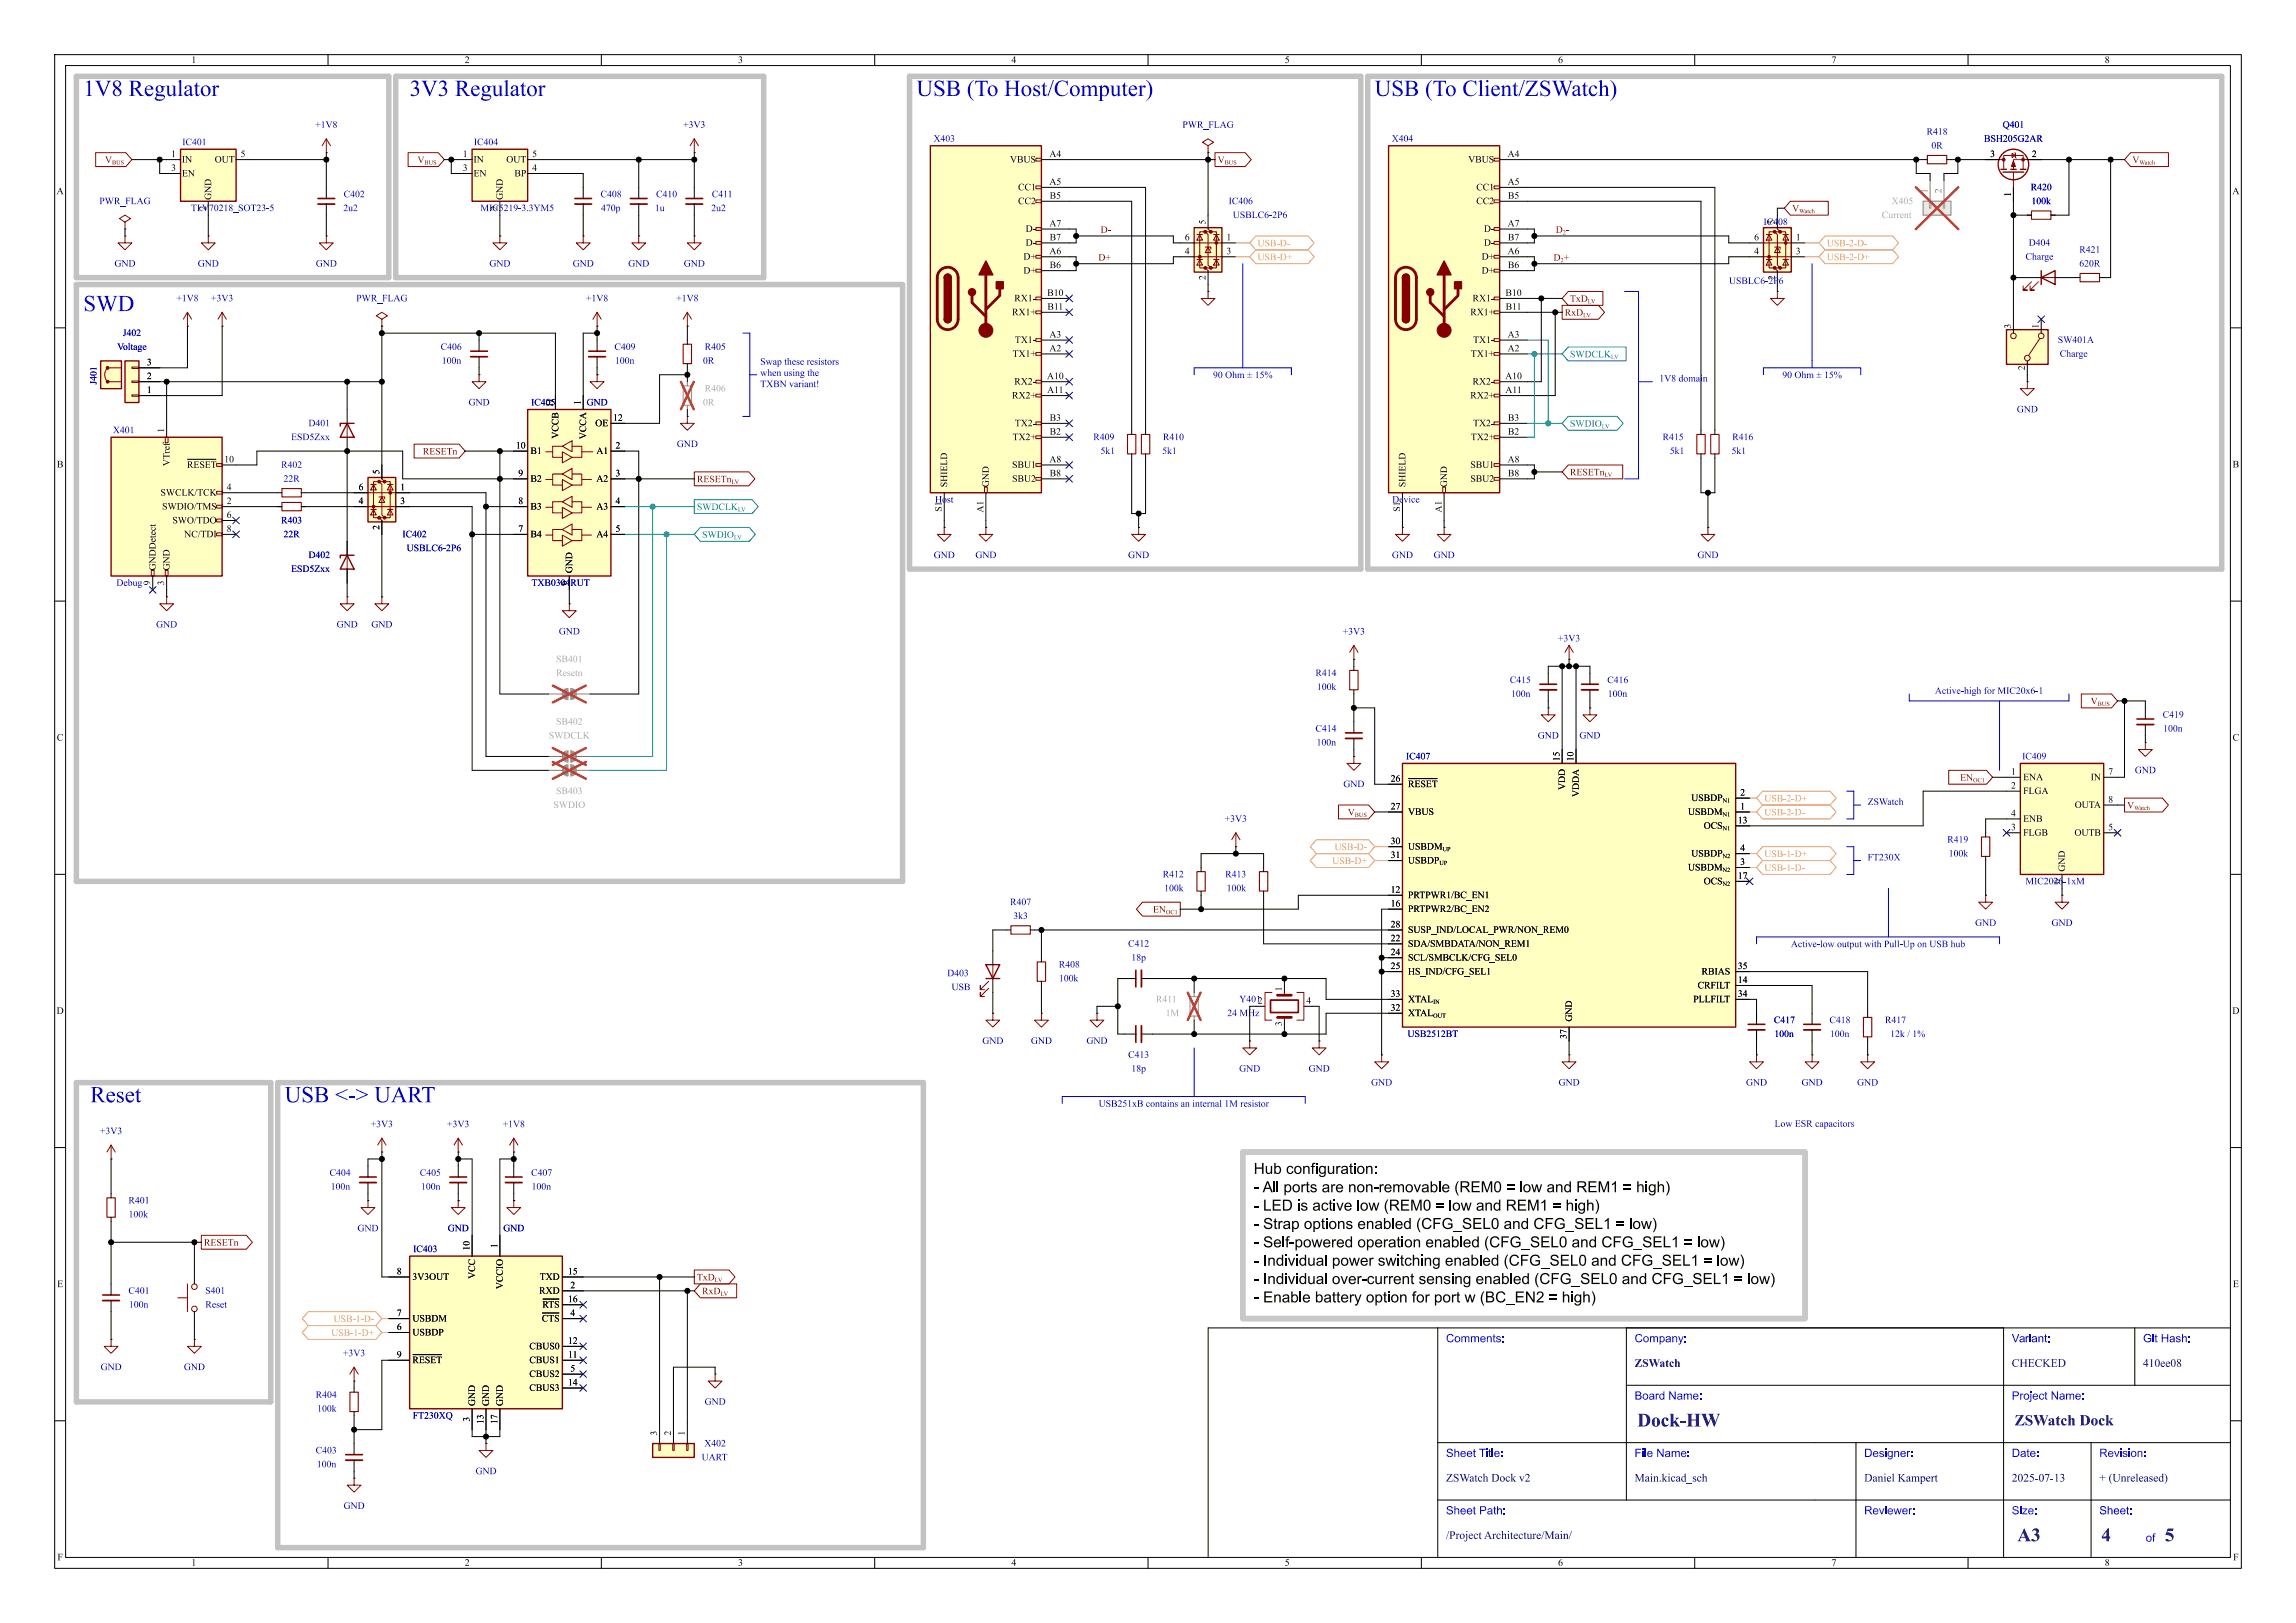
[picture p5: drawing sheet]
<svg xmlns="http://www.w3.org/2000/svg" width="420mm" height="297mm" viewBox="0 0 420 297" stroke-linecap="round" stroke-linejoin="round" font-family="sans-serif">
<defs><g id="words">
<g font-size="4.2" fill="#0000c2">
<text x="15.2" y="18.1">1V8 Regulator</text>
<text x="74.9" y="18.1">3V3 Regulator</text>
<text x="167.6" y="18.1">USB(ToHost/Computer)</text>
<text x="251.5" y="18.1">USB(ToClient/ZSWatch)</text>
<text x="15.2" y="57.4">SWD</text>
<text x="16.5" y="202.2">Reset</text>
<text x="52.1" y="202.2">USB&lt;-&gt; UART</text>
</g>
<g font-size="3.5" fill="#00007f">
<text x="299.5" y="261.9">Dock-HW</text>
<text x="369" y="282.9">A3</text>
<text x="384.4" y="282.9">4</text>
<text x="396" y="282.9">5</text>
</g>
<g font-size="2.8">
<text x="229.3" y="216">Hub configuration:</text>
<text x="229.3" y="219.3">- All ports are non-removable (REM0 = low and REM1 = high)</text>
<text x="229.3" y="229.4">- Self-powered operation enabled (CFG_SEL0 and CFG_SEL1 = low)</text>
<text x="229.3" y="236.1">- Individual over-current sensing enabled (CFG_SEL0 and CFG_SEL1 = low)</text>
</g>
<text font-size="2.8" fill="#00007f" x="368.5" y="261.6">ZSWatchDock</text>
<g font-size="2.1" fill="#00f">
<text x="264.5" y="246.2">Comments:</text>
<text x="299" y="246.2">Company:</text>
<text x="368" y="246.2">Variant:</text>
<text x="392" y="246.2">Git Hash:</text>
<text x="299" y="256.7">Board Name:</text>
<text x="368" y="256.7">Project Name:</text>
<text x="264.5" y="267.2">Sheet Title:</text>
<text x="299" y="267.2">File Name:</text>
<text x="341" y="267.2">Designer:</text>
<text x="368" y="267.2">Date:</text>
<text x="384" y="267.2">Revision:</text>
<text x="264.5" y="277.7">Sheet Path:</text>
<text x="341" y="277.7">Reviewer:</text>
<text x="368" y="277.7">Size:</text>
<text x="384" y="277.7">Sheet:</text>
<text x="392.5" y="282.7">of</text>
</g>
<g font-size="2.1" fill="#00007f">
<text x="299" y="250.7">ZSWatch</text>
<text x="368" y="250.7">CHECKED</text>
<text x="392" y="250.7">410ee08</text>
<text x="264.5" y="271.7">ZSWatchDockv2</text>
<text x="299" y="271.7">Main.kicad_sch</text>
<text x="341" y="271.7">DanielKampert</text>
<text x="368" y="271.7">2025-07-13</text>
<text x="384" y="271.7">+ (Unreleased)</text>
<text x="264.5" y="282.2">/ProjectArchitecture/Main/</text>
</g>
<g font-size="1.8">
<text x="35" y="12">1</text>
<text x="85" y="12">2</text>
<text x="135" y="12">3</text>
<text x="185" y="12">4</text>
<text x="235" y="12">5</text>
<text x="285" y="12">6</text>
<text x="335" y="12">7</text>
<text x="385" y="12">8</text>
<text x="31.3" y="29">1</text>
<text x="44" y="29">5</text>
<text x="84.6" y="29">1</text>
<text x="97.3" y="29">5</text>
<text x="192" y="29">A4</text>
<text x="275.8" y="29">A4</text>
<text x="364" y="29">3</text>
<text x="371.7" y="29">2</text>
<text x="31.3" y="31.5">3</text>
<text x="33.3" y="30.2">IN</text>
<text x="33.3" y="32.7">EN</text>
<text x="39.3" y="30.2">OUT</text>
<text x="76.4" y="30.3">V_{BUS}</text>
<text x="84.6" y="31.5">3</text>
<text x="86.6" y="30.2">IN</text>
<text x="86.6" y="32.7">EN</text>
<text x="92.6" y="30.2">OUT</text>
<text x="94.1" y="32.7">BP</text>
<text x="97.3" y="31.5">4</text>
<text x="184.7" y="30.2">VBUS</text>
<text x="186.2" y="35.3">CC1</text>
<text x="192" y="34">A5</text>
<text x="268.6" y="30.2">VBUS</text>
<text x="270" y="35.3">CC1</text>
<text x="275.8" y="34">A5</text>
<text x="10.3" y="36">A</text>
<text x="39.1" y="36.6" transform="rotate(-90 39.1 36.6)">GND</text>
<text x="92.4" y="36.6" transform="rotate(-90 92.4 36.6)">GND</text>
<text x="186.2" y="37.8">CC2</text>
<text x="192" y="41.7">A7</text>
<text x="192" y="36.6">B5</text>
<text x="220.7" y="41.1" transform="rotate(-90 220.7 41.1)">5</text>
<text x="270" y="37.8">CC2</text>
<text x="275.8" y="41.7">A7</text>
<text x="275.8" y="36.6">B5</text>
<text x="368" y="36" transform="rotate(-90 368 36)">1</text>
<text x="408.3" y="36">A</text>
<text x="187.2" y="48">D+</text>
<text x="187.6" y="42.9">D-</text>
<text x="187.6" y="45.4">D-</text>
<text x="192" y="46.7">A6</text>
<text x="192" y="44.2">B7</text>
<text x="216.7" y="44.2">6</text>
<text x="216.7" y="46.7">4</text>
<text x="224.3" y="44.2">1</text>
<text x="224.3" y="46.7">3</text>
<text x="271" y="48">D+</text>
<text x="271.4" y="42.9">D-</text>
<text x="271.4" y="45.4">D-</text>
<text x="275.8" y="46.7">A6</text>
<text x="275.8" y="44.2">B7</text>
<text x="320.9" y="44.2">6</text>
<text x="320.9" y="46.7">4</text>
<text x="328.5" y="44.2">1</text>
<text x="328.5" y="46.7">3</text>
<text x="187.2" y="50.5">D+</text>
<text x="192" y="49.3">B6</text>
<text x="220.7" y="51.2" transform="rotate(-90 220.7 51.2)">2</text>
<text x="271" y="50.5">D+</text>
<text x="275.8" y="49.3">B6</text>
<text x="324.9" y="51.2" transform="rotate(-90 324.9 51.2)">2</text>
<text x="185.1" y="58.1">RX1+</text>
<text x="185.5" y="55.6">RX1-</text>
<text x="191.6" y="54.4">B10</text>
<text x="191.6" y="56.9">B11</text>
<text x="268.9" y="58.1">RX1+</text>
<text x="269.4" y="55.6">RX1-</text>
<text x="275.4" y="54.4">B10</text>
<text x="275.4" y="56.9">B11</text>
<text x="185.2" y="65.8">TX1+</text>
<text x="185.6" y="63.2">TX1-</text>
<text x="192" y="62">A3</text>
<text x="192" y="64.5">A2</text>
<text x="269" y="65.8">TX1+</text>
<text x="269.5" y="63.2">TX1-</text>
<text x="275.8" y="62">A3</text>
<text x="275.8" y="64.5">A2</text>
<text x="368" y="60.1" transform="rotate(-90 368 60.1)">3</text>
<text x="373.1" y="60.1" transform="rotate(-90 373.1 60.1)">1</text>
<text x="26.9" y="69.6">2</text>
<text x="26.9" y="67.1">3</text>
<text x="185.5" y="70.8">RX2-</text>
<text x="191.5" y="69.6">A10</text>
<text x="269.4" y="70.8">RX2-</text>
<text x="275.3" y="69.6">A10</text>
<text x="370.6" y="67.8" transform="rotate(-90 370.6 67.8)">2</text>
<text x="26.9" y="72.1">1</text>
<text x="101.3" y="74.5" transform="rotate(-90 101.3 74.5)">11</text>
<text x="106.4" y="74.1" transform="rotate(-90 106.4 74.1)">1</text>
<text x="112.1" y="77.2">12</text>
<text x="185.1" y="73.4">RX2+</text>
<text x="191.5" y="72.1">A11</text>
<text x="192" y="77.2">B3</text>
<text x="268.9" y="73.4">RX2+</text>
<text x="275.4" y="72.1">A11</text>
<text x="275.8" y="77.2">B3</text>
<text x="30.2" y="79.2" transform="rotate(-90 30.2 79.2)">1</text>
<text x="94.4" y="82.3">10</text>
<text x="97" y="83.5">B1</text>
<text x="102.6" y="80.3" transform="rotate(-90 102.6 80.3)">VCCB</text>
<text x="107.7" y="80.4" transform="rotate(-90 107.7 80.4)">VCCA</text>
<text x="108.9" y="78.5">OE</text>
<text x="109.1" y="83.5">A1</text>
<text x="112.6" y="82.3">2</text>
<text x="185.2" y="81">TX2+</text>
<text x="185.6" y="78.5">TX2-</text>
<text x="192" y="79.8">B2</text>
<text x="269" y="81">TX2+</text>
<text x="269.5" y="78.5">TX2-</text>
<text x="275.8" y="79.8">B2</text>
<text x="10.4" y="86">B</text>
<text x="31.5" y="85.3" transform="rotate(-90 31.5 85.3)">VTref</text>
<text x="34.2" y="86.1">~{RESET}</text>
<text x="41" y="84.8">10</text>
<text x="41.5" y="89.9">4</text>
<text x="65.6" y="89.9">6</text>
<text x="69.6" y="86.8" transform="rotate(-90 69.6 86.8)">5</text>
<text x="73.2" y="89.9">1</text>
<text x="94.8" y="87.4">9</text>
<text x="97" y="88.6">B2</text>
<text x="109.1" y="88.6">A2</text>
<text x="112.6" y="87.4">3</text>
<text x="173.7" y="89.2" transform="rotate(-90 173.7 89.2)">SHIELD</text>
<text x="181.3" y="89.2" transform="rotate(-90 181.3 89.2)">GND</text>
<text x="185.1" y="86.1">SBU1</text>
<text x="185.1" y="88.6">SBU2</text>
<text x="192" y="84.8">A8</text>
<text x="192" y="87.4">B8</text>
<text x="257.5" y="89.2" transform="rotate(-90 257.5 89.2)">SHIELD</text>
<text x="265.1" y="89.2" transform="rotate(-90 265.1 89.2)">GND</text>
<text x="269" y="86.1">SBU1</text>
<text x="269" y="88.6">SBU2</text>
<text x="275.8" y="84.8">A8</text>
<text x="275.8" y="87.4">B8</text>
<text x="408.4" y="86">B</text>
<text x="29.4" y="91.2">SWCLK/TCK</text>
<text x="29.7" y="93.7">SWDIO/TMS</text>
<text x="41.5" y="92.5">2</text>
<text x="41.5" y="95">6</text>
<text x="65.6" y="92.5">4</text>
<text x="73.2" y="92.5">3</text>
<text x="94.8" y="92.5">8</text>
<text x="97" y="93.7">B3</text>
<text x="109.1" y="93.7">A3</text>
<text x="112.6" y="92.5">4</text>
<text x="172.5" y="93.6" transform="rotate(-90 172.5 93.6)">S1</text>
<text x="180.1" y="93.8" transform="rotate(-90 180.1 93.8)">A1</text>
<text x="256.3" y="93.6" transform="rotate(-90 256.3 93.6)">S1</text>
<text x="263.9" y="93.8" transform="rotate(-90 263.9 93.8)">A1</text>
<text x="31.5" y="96.2">SWO/TDO</text>
<text x="33.7" y="98.8">NC/TDI</text>
<text x="41.5" y="97.5">8</text>
<text x="69.6" y="97" transform="rotate(-90 69.6 97)">2</text>
<text x="94.8" y="97.5">7</text>
<text x="97" y="98.8">B4</text>
<text x="109.1" y="98.8">A4</text>
<text x="112.6" y="97.5">5</text>
<text x="27.7" y="107.1" transform="rotate(-90 27.7 107.1)">9</text>
<text x="28.9" y="104.4" transform="rotate(-90 28.9 104.4)">GNDDetect</text>
<text x="30.2" y="107.1" transform="rotate(-90 30.2 107.1)">3</text>
<text x="31.5" y="104.4" transform="rotate(-90 31.5 104.4)">GND</text>
<text x="103.9" y="107.1" transform="rotate(-90 103.9 107.1)">6</text>
<text x="105.1" y="104.9" transform="rotate(-90 105.1 104.9)">GND</text>
<text x="382.4" y="129.3">V_{BUS}</text>
<text x="10.4" y="136">C</text>
<text x="408.4" y="136">C</text>
<text x="254.4" y="143.3">26</text>
<text x="285.5" y="139.3" transform="rotate(-90 285.5 139.3)">15</text>
<text x="288" y="139.3" transform="rotate(-90 288 139.3)">10</text>
<text x="358.5" y="143.3">EN_{OC1}</text>
<text x="367.9" y="142">1</text>
<text x="370.1" y="143.2">ENA</text>
<text x="382.4" y="143.2">IN</text>
<text x="385.6" y="142">7</text>
<text x="246.5" y="149.7">V_{BUS}</text>
<text x="254.4" y="148.3">27</text>
<text x="257.6" y="144.5">~{RESET}</text>
<text x="257.6" y="149.6">VBUS</text>
<text x="286.7" y="144.6" transform="rotate(-90 286.7 144.6)">VDD</text>
<text x="289.3" y="145.8" transform="rotate(-90 289.3 145.8)">VDDA</text>
<text x="308.8" y="149.6">USBDM_{N1}</text>
<text x="309.4" y="147">USBDP_{N1}</text>
<text x="318.3" y="145.8">2</text>
<text x="318.3" y="148.3">1</text>
<text x="367.9" y="144.5">2</text>
<text x="367.9" y="149.6">4</text>
<text x="370.1" y="145.8">FLGA</text>
<text x="379.5" y="148.3">OUTA</text>
<text x="385.6" y="147.1">8</text>
<text x="254.4" y="154.7">30</text>
<text x="257.6" y="155.9">USBDM_{UP}</text>
<text x="311.6" y="152.1">OCS_{N1}</text>
<text x="317.9" y="150.9">13</text>
<text x="318.3" y="156">4</text>
<text x="367.9" y="152.1">3</text>
<text x="370.1" y="150.8">ENB</text>
<text x="370.1" y="153.4">FLGB</text>
<text x="379.5" y="153.4">OUTB</text>
<text x="385.6" y="152.1">5</text>
<text x="254.4" y="157.2">31</text>
<text x="257.6" y="158.5">USBDP_{UP}</text>
<text x="308.8" y="159.7">USBDM_{N2}</text>
<text x="309.4" y="157.2">USBDP_{N2}</text>
<text x="317.9" y="161">17</text>
<text x="318.3" y="158.5">3</text>
<text x="378.2" y="159.5" transform="rotate(-90 378.2 159.5)">GND</text>
<text x="254.4" y="166.1">16</text>
<text x="254.4" y="163.6">12</text>
<text x="257.6" y="167.4">PRTPWR2/BC_EN2</text>
<text x="257.6" y="164.8">PRTPWR1/BC_EN1</text>
<text x="311.6" y="162.3">OCS_{N2}</text>
<text x="254.4" y="169.9">28</text>
<text x="254.4" y="172.5">22</text>
<text x="257.6" y="171.2">SUSP_IND/LOCAL_PWR/NON_REM0</text>
<text x="257.6" y="173.7">SDA/SMBDATA/NON_REM1</text>
<text x="254.4" y="175">24</text>
<text x="254.4" y="177.5">25</text>
<text x="257.6" y="176.2">SCL/SMBCLK/CFG_SEL0</text>
<text x="257.6" y="178.8">HS_IND/CFG_SEL1</text>
<text x="311.3" y="178.8">RBIAS</text>
<text x="317.9" y="177.5">35</text>
<text x="226.7" y="183.9">Y4012</text>
<text x="234.7" y="181.4" transform="rotate(-90 234.7 181.4)">1</text>
<text x="239" y="183.9">4</text>
<text x="254.4" y="182.6">33</text>
<text x="254.4" y="185.2">32</text>
<text x="257.6" y="183.9">XTAL_{IN}</text>
<text x="309.7" y="183.9">PLLFILT</text>
<text x="310.5" y="181.3">CRFILT</text>
<text x="317.9" y="180.1">14</text>
<text x="317.9" y="182.6">34</text>
<text x="10.3" y="186">D</text>
<text x="234.7" y="187.8" transform="rotate(-90 234.7 187.8)">3</text>
<text x="257.6" y="186.4">XTAL_{OUT}</text>
<text x="286.8" y="190.1" transform="rotate(-90 286.8 190.1)">37</text>
<text x="288" y="186.9" transform="rotate(-90 288 186.9)">GND</text>
<text x="408.3" y="186">D</text>
<text x="72.6" y="233.4">8</text>
<text x="86.1" y="228.9" transform="rotate(-90 86.1 228.9)">10</text>
<text x="91.2" y="228.4" transform="rotate(-90 91.2 228.4)">1</text>
<text x="103.9" y="233.4">15</text>
<text x="10.4" y="236">E</text>
<text x="75.4" y="234.7">3V3OUT</text>
<text x="87.3" y="234" transform="rotate(-90 87.3 234)">VCC</text>
<text x="92.4" y="235.9" transform="rotate(-90 92.4 235.9)">VCCIO</text>
<text x="98.6" y="237.2">RXD</text>
<text x="98.7" y="234.7">TXD</text>
<text x="99.2" y="239.7">~{RTS}</text>
<text x="103.9" y="238.5">16</text>
<text x="104.3" y="236">2</text>
<text x="408.4" y="236">E</text>
<text x="72.6" y="241">7</text>
<text x="72.6" y="243.6">6</text>
<text x="75.4" y="242.3">USBDM</text>
<text x="75.4" y="244.8">USBDP</text>
<text x="99.1" y="242.3">~{CTS}</text>
<text x="104.3" y="241">4</text>
<text x="72.6" y="248.7">9</text>
<text x="75.4" y="249.9">~{RESET}</text>
<text x="96.8" y="247.4">CBUS0</text>
<text x="96.8" y="249.9">CBUS1</text>
<text x="103.9" y="246.1">12</text>
<text x="103.9" y="248.7">11</text>
<text x="104.3" y="251.2">5</text>
<text x="87.3" y="257.3" transform="rotate(-90 87.3 257.3)">GND</text>
<text x="89.9" y="257.3" transform="rotate(-90 89.9 257.3)">GND</text>
<text x="92.4" y="257.3" transform="rotate(-90 92.4 257.3)">GND</text>
<text x="96.8" y="252.4">CBUS2</text>
<text x="96.8" y="255">CBUS3</text>
<text x="103.9" y="253.7">14</text>
<text x="86.1" y="260.2" transform="rotate(-90 86.1 260.2)">3</text>
<text x="88.6" y="260.6" transform="rotate(-90 88.6 260.6)">13</text>
<text x="91.2" y="260.6" transform="rotate(-90 91.2 260.6)">17</text>
<text x="120.4" y="262.7" transform="rotate(-90 120.4 262.7)">3</text>
<text x="122.9" y="262.7" transform="rotate(-90 122.9 262.7)">2</text>
<text x="125.5" y="262.7" transform="rotate(-90 125.5 262.7)">1</text>
<text x="10.5" y="286">F</text>
<text x="35" y="287">1</text>
<text x="85" y="287">2</text>
<text x="135" y="287">3</text>
<text x="185" y="287">4</text>
<text x="235" y="287">5</text>
<text x="285" y="287">6</text>
<text x="335" y="287">7</text>
<text x="385" y="287">8</text>
<text x="408.5" y="286">F</text>
</g>
<g font-size="1.8" fill="#0000c2">
<text x="57.7" y="23.8">+1V8</text>
<text x="125" y="23.8">+3V3</text>
<text x="216.3" y="23.8">PWR_FLAG</text>
<text x="366.3" y="23.8">Q401</text>
<text x="33.3" y="27">IC401</text>
<text x="86.7" y="27">IC404</text>
<text x="170.7" y="26.4">X403</text>
<text x="254.6" y="26.4">X404</text>
<text x="352.4" y="25.1">R418</text>
<text x="353.3" y="27.7">0R</text>
<text x="362.9" y="26.4">BSH205G2AR</text>
<text x="371.5" y="35.3">R420</text>
<text x="18.2" y="37.8">PWR_FLAG</text>
<text x="34.9" y="39.1">TLV70218_SOT23-5</text>
<text x="37.8" y="38.5" transform="rotate(-90 37.8 38.5)">2</text>
<text x="62.8" y="39.1">2u2</text>
<text x="62.9" y="36.6">C402</text>
<text x="87.9" y="39.1">MIC5219-3.3YM5</text>
<text x="91.2" y="38.5" transform="rotate(-90 91.2 38.5)">2</text>
<text x="109.9" y="36.6">C408</text>
<text x="109.9" y="39.1">470p</text>
<text x="119.8" y="39.1">1u</text>
<text x="120" y="36.6">C410</text>
<text x="130.1" y="39.1">2u2</text>
<text x="130.2" y="36.6">C411</text>
<text x="224.7" y="37.8">IC406</text>
<text x="225.5" y="40.4">USBLC6-2P6</text>
<text x="322.6" y="41.6">IC408</text>
<text x="324.9" y="41.1" transform="rotate(-90 324.9 41.1)">5</text>
<text x="371.6" y="37.8">100k</text>
<text x="370.5" y="48">Charge</text>
<text x="371.1" y="45.4">D404</text>
<text x="380.3" y="46.7">R421</text>
<text x="20.9" y="49.2">GND</text>
<text x="36.2" y="49.2">GND</text>
<text x="57.8" y="49.2">GND</text>
<text x="89.5" y="49.2">GND</text>
<text x="104.8" y="49.2">GND</text>
<text x="114.9" y="49.2">GND</text>
<text x="125.1" y="49.2">GND</text>
<text x="316.3" y="52.4">USBLC6-2P6</text>
<text x="380.3" y="49.2">620R</text>
<text x="32.3" y="55.6">+1V8</text>
<text x="38.6" y="55.6">+3V3</text>
<text x="65.2" y="55.6">PWR_FLAG</text>
<text x="107.2" y="55.6">+1V8</text>
<text x="123.7" y="55.6">+1V8</text>
<text x="21.4" y="64.5">Voltage</text>
<text x="22.5" y="61.9">J402</text>
<text x="80.6" y="64.5">C406</text>
<text x="112.4" y="64.5">C409</text>
<text x="128.9" y="64.5">R405</text>
<text x="376.4" y="63.2">SW401A</text>
<text x="376.8" y="65.8">Charge</text>
<text x="18.1" y="70.4" transform="rotate(-90 18.1 70.4)">J401</text>
<text x="80.8" y="67">100n</text>
<text x="112.5" y="67">100n</text>
<text x="128.6" y="67">0R</text>
<text x="139.1" y="67.5">Swaptheseresistors</text>
<text x="139.1" y="69.5">whenusingthe</text>
<text x="139.1" y="71.5">TXBN variant!</text>
<text x="229.5" y="69.6">15%</text>
<text x="303.5" y="70.3">1V8 domain</text>
<text x="333.7" y="69.6">15%</text>
<text x="85.7" y="74.6">GND</text>
<text x="97.2" y="74.6">IC405</text>
<text x="107.3" y="74.6">GND</text>
<text x="368.9" y="75.9">GND</text>
<text x="20.6" y="79.7">X401</text>
<text x="53.2" y="81">ESD5Zxx</text>
<text x="56.4" y="78.5">D401</text>
<text x="123.8" y="82.3">GND</text>
<text x="200" y="81">R409</text>
<text x="201.3" y="83.5">5k1</text>
<text x="212.6" y="83.5">5k1</text>
<text x="212.7" y="81">R410</text>
<text x="304.1" y="81">R415</text>
<text x="305.4" y="83.5">5k1</text>
<text x="316.7" y="83.5">5k1</text>
<text x="316.9" y="81">R416</text>
<text x="51.4" y="86.1">R402</text>
<text x="51.9" y="88.6">22R</text>
<text x="171" y="92.4">Host</text>
<text x="254.7" y="92.4">Device</text>
<text x="51.4" y="96.2">R403</text>
<text x="51.9" y="98.8">22R</text>
<text x="73.6" y="98.8">IC402</text>
<text x="74.4" y="101.3">USBLC6-2P6</text>
<text x="21.3" y="107.7">Debug</text>
<text x="53.2" y="105.1">ESD5Zxx</text>
<text x="56.4" y="102.6">D402</text>
<text x="97.2" y="107.7">TXB0304RUT</text>
<text x="170.8" y="102.6">GND</text>
<text x="178.4" y="102.6">GND</text>
<text x="206.4" y="102.6">GND</text>
<text x="254.6" y="102.6">GND</text>
<text x="262.2" y="102.6">GND</text>
<text x="310.5" y="102.6">GND</text>
<text x="28.6" y="115.3">GND</text>
<text x="61.6" y="115.3">GND</text>
<text x="67.9" y="115.3">GND</text>
<text x="102.2" y="116.6">GND</text>
<text x="245.6" y="116.6">+3V3</text>
<text x="285" y="117.8">+3V3</text>
<text x="240.6" y="124.2">R414</text>
<text x="276.2" y="125.5">C415</text>
<text x="294" y="125.5">C416</text>
<text x="240.9" y="126.7">100k</text>
<text x="276.4" y="128">100n</text>
<text x="294.1" y="128">100n</text>
<text x="353.9" y="127.4">Active-highfor MIC20x6-1</text>
<text x="395.6" y="131.8">C419</text>
<text x="240.6" y="134.3">C414</text>
<text x="240.8" y="136.9">100n</text>
<text x="281.3" y="135.6">GND</text>
<text x="288.9" y="135.6">GND</text>
<text x="395.7" y="134.3">100n</text>
<text x="257.2" y="139.4">IC407</text>
<text x="369.9" y="139.4">IC409</text>
<text x="390.5" y="142">GND</text>
<text x="245.7" y="144.5">GND</text>
<text x="341.6" y="147.7">ZSWatch</text>
<text x="224" y="150.8">+3V3</text>
<text x="356.2" y="154.7">R419</text>
<text x="212.7" y="161">R412</text>
<text x="224.1" y="161">R413</text>
<text x="341.6" y="157.9">FT230X</text>
<text x="356.5" y="157.2">100k</text>
<text x="376.9" y="161.7" transform="rotate(-90 376.9 161.7)">6</text>
<text x="184.8" y="166.1">R407</text>
<text x="213" y="163.5">100k</text>
<text x="224.4" y="163.5">100k</text>
<text x="370.5" y="162.3">MIC2026-1xM</text>
<text x="185.4" y="168.6">3k3</text>
<text x="206.4" y="173.7">C412</text>
<text x="327.6" y="173.8">Active-low outputwith Pull-UponUSBhub</text>
<text x="361.3" y="169.9">GND</text>
<text x="375.3" y="169.9">GND</text>
<text x="173.3" y="179.1">D403</text>
<text x="193.7" y="177.5">R408</text>
<text x="207" y="176.2">18p</text>
<text x="174.1" y="181.6">USB</text>
<text x="193.7" y="180.1">100k</text>
<text x="179.7" y="191.5">GND</text>
<text x="188.6" y="191.5">GND</text>
<text x="198.7" y="191.5">GND</text>
<text x="224.5" y="186.4">24MHz</text>
<text x="257.5" y="190.2">USB2512BT</text>
<text x="324.5" y="187.7">C417</text>
<text x="324.6" y="190.2">100n</text>
<text x="334.6" y="187.7">C418</text>
<text x="334.7" y="190.2">100n</text>
<text x="344.8" y="187.7">R417</text>
<text x="345.8" y="190.2">12k/ 1%</text>
<text x="206.4" y="194">C413</text>
<text x="207" y="196.6">18p</text>
<text x="226.7" y="196.6">GND</text>
<text x="239.4" y="196.6">GND</text>
<text x="201" y="203">USB251xBcontainsaninternal1M resistor</text>
<text x="250.8" y="199.1">GND</text>
<text x="285.1" y="199.1">GND</text>
<text x="319.4" y="199.1">GND</text>
<text x="329.5" y="199.1">GND</text>
<text x="339.7" y="199.1">GND</text>
<text x="18.3" y="208">+3V3</text>
<text x="67.8" y="206.7">+3V3</text>
<text x="81.8" y="206.7">+3V3</text>
<text x="91.9" y="206.7">+1V8</text>
<text x="324.6" y="206.9">Low ESRcapacitors</text>
<text x="60.3" y="215.6">C404</text>
<text x="76.8" y="215.6">C405</text>
<text x="97.2" y="215.6">C407</text>
<text x="23.5" y="220.7">R401</text>
<text x="60.5" y="218.2">100n</text>
<text x="77" y="218.2">100n</text>
<text x="97.2" y="218.2">100n</text>
<text x="23.5" y="223.2">100k</text>
<text x="65.4" y="225.8">GND</text>
<text x="81.9" y="225.8">GND</text>
<text x="92.1" y="225.8">GND</text>
<text x="75.6" y="229.6">IC403</text>
<text x="23.5" y="237.2">C401</text>
<text x="23.6" y="239.8">100n</text>
<text x="37.5" y="237.2">S401</text>
<text x="37.6" y="239.7">Reset</text>
<text x="18.4" y="251.2">GND</text>
<text x="33.6" y="251.2">GND</text>
<text x="62.7" y="248.6">+3V3</text>
<text x="57.7" y="256.3">R404</text>
<text x="128.9" y="257.5">GND</text>
<text x="58" y="258.8">100k</text>
<text x="75.5" y="260.1">FT230XQ</text>
<text x="57.7" y="266.4">C403</text>
<text x="58" y="269">100n</text>
<text x="128.3" y="267.7">UART</text>
<text x="128.8" y="265.1">X402</text>
<text x="87" y="270.2">GND</text>
<text x="62.8" y="276.6">GND</text>
</g>
<g font-size="1.8" fill="#7a7a77">
<text x="352.8" y="35.4" transform="rotate(-90 352.8 35.4)">1</text>
<text x="355.3" y="35.4" transform="rotate(-90 355.3 35.4)">2</text>
</g>
<g font-size="1.8" fill="#840000">
<text x="390" y="30.3">V_{Watch}</text>
<text x="327.8" y="39.2">V_{Watch}</text>
<text x="200.9" y="47.9">D+</text>
<text x="201.3" y="42.8">D-</text>
<text x="286.2" y="58.2">RxD_{LV}</text>
<text x="287.2" y="55.7">TxD_{LV}</text>
<text x="77.3" y="83.6">RESETn</text>
<text x="127.5" y="88.7">RESETn_{LV}</text>
<text x="287.2" y="87.4">RESETn_{LV}</text>
<text x="389.1" y="148.4">V_{Watch}</text>
<text x="210.9" y="167.4">EN_{OC1}</text>
<text x="37.3" y="228.4">RESETn</text>
<text x="127.5" y="234.8">TxD_{LV}</text>
<text x="128.4" y="237.3">RxD_{LV}</text>
</g>
<g font-size="1.8" fill="#abaaa8">
<text x="344.2" y="40.4">Current</text>
<text x="346" y="37.8">X405</text>
<text x="128.6" y="74.6">0R</text>
<text x="128.9" y="72.1">R406</text>
<text x="101.7" y="121.6">SB401</text>
<text x="101.7" y="124.2">Resetn</text>
<text x="100.4" y="135.6">SWDCLK</text>
<text x="101.7" y="133.1">SB402</text>
<text x="101.2" y="148.3">SWDIO</text>
<text x="101.7" y="145.8">SB403</text>
<text x="211.4" y="183.9">R411</text>
<text x="213.2" y="186.4">1M</text>
</g>
<g font-size="1.8" fill="#ffa049">
<text x="230" y="45.5">USB-D-</text>
<text x="334.2" y="45.5">USB-2-D-</text>
<text x="230" y="48.1">USB-D+</text>
<text x="334.2" y="48.1">USB-2-D+</text>
<text x="322.7" y="149.7">USB-2-D-</text>
<text x="322.7" y="147.1">USB-2-D+</text>
<text x="243.7" y="158.6">USB-D+</text>
<text x="244.1" y="156">USB-D-</text>
<text x="322.7" y="159.8">USB-1-D-</text>
<text x="322.7" y="157.3">USB-1-D+</text>
<text x="60.6" y="244.9">USB-1-D+</text>
<text x="61" y="242.4">USB-1-D-</text>
</g>
<g font-size="1.8" fill="#008484">
<text x="287.2" y="65.8">SWDCLK_{LV}</text>
<text x="287.2" y="78.5">SWDIO_{LV}</text>
<text x="127.5" y="93.8">SWDCLK_{LV}</text>
<text x="128.4" y="98.9">SWDIO_{LV}</text>
</g>
</g></defs>
<g fill="none" stroke="#000" stroke-width=".18">
<path d="M10 10h400v277h-400zM12 12h396v273h-396zM60 10v2M110 10v2M160 10v2M210 10v2M260 10v2M310 10v2M360 10v2M59.7 27.9h.1M59.7 34.3v2M59.7 37.3v2.1"/>
<path d="M59.7 43.2h.1M10 60h2M408 60h2M312.4 96.5h.1M10 110h2M408 110h2M287 120.7h.1M10 160h2M408 160h2M205.7 179.1h2.1M208.8 179.1h2M331.5 193h.1"/>
<path d="M341.6 193h.1M10 210h2M67.3 219.7h.1M67.3 213.4v2M67.3 216.4v2M408 210h2M263 243v42M297.5 253.5h110.5M297.5 243v31.5M366.5 243v42M390.5 243v10.5M408 243h-187v42"/>
<path d="M10 260h2M263 274.5h145M263 264h145M339.5 264v21M382.5 264v21M408 260h2M60 285v2M110 285v2M160 285v2M210 285v2M260 285v2M310 285v2"/>
<path d="M360 285v2"/>
</g>
<path d="M58.2 36.3h3M207.8 177.5v3.1M65.8 215.4h3" fill="none" stroke="#840000" stroke-width=".3"/>
<path d="M58.2 37.3h3M208.8 177.5v3.1M65.8 216.4h3" fill="none" stroke="#840000" stroke-width=".33"/>
<path d="M59.7 25.4l.8 1.3M59.7 25.4l-.8 1.3M59.7 25.4v2.5M59.7 43.2v1.3h1.3l-1.3 1.2-1.3-1.2h1.3M312.4 96.5v1.3h1.3l-1.3 1.3-1.3-1.3h1.3M287 118.1l-.7 1.3M287 118.1l.8 1.3M287 118.1v2.6M331.5 193v1.3h-1.3l1.3 1.3 1.2-1.3h-1.2M341.6 193v1.3h-1.2l1.2 1.3 1.3-1.3h-1.3M67.3 219.7v1.3h1.3l-1.3 1.2-1.3-1.2h1.3" fill="none" stroke="#840000" stroke-width=".18"/>
<path d="M217.7 182.4h1.5v3.5h-1.5z" fill="none" stroke="#9c9b98" stroke-width=".2"/>
<path d="M218.4 181.6v.8M218.4 185.9v.8" fill="none" stroke="#7a7a77" stroke-width=".18"/>
<path d="M217.3 181.6l2.3 5.1M219.6 181.6l-2.3 5.1" fill="none" stroke="#e12e31" stroke-width=".46"/>
<path d="M33 27.3h10.2v9.5h-10.2z" fill="#ffffc2"/>
<path d="M33 27.3h10.2v9.5h-10.2z" fill="none" stroke="#840000" stroke-width=".25"/>
<path d="M30.5 29.2h2.5M30.5 31.8h2.5M38.1 36.8v2.6M43.2 29.2h2.5" fill="none" stroke="#000" stroke-width=".18"/>
<path d="M218.4 41.7h5.1v8.1h-5.1z" fill="#ffffc2"/>
<g fill="#840000" stroke="#840000" stroke-width=".18">
<circle cx="222.5" cy="44.4" r=".25"/>
<circle cx="221.5" cy="42.4" r=".25"/>
<circle cx="221.5" cy="49" r=".25"/>
<circle cx="220.5" cy="42.4" r=".25"/>
<circle cx="220.5" cy="49" r=".25"/>
<circle cx="219.5" cy="47" r=".25"/>
</g>
<g fill="none" stroke="#840000" stroke-width=".18">
<path d="M221 26.7l1-.7-1-.6-1 .6 1 .7v1.2M218.4 44.5h5.1M218.4 47h5.1M218.9 47.5h1.1M218.9 42.9h1.1M219.5 42.9l.5 1h-1.1zM219.5 47.5l.5 1h-1.1zM220.5 45.2h1v.4M220.5 42.4h-1v6.6h1M221 41.9l.5 .5h-1l.5 .5v5.6l.5 .5h-1l.5 .5M221 45.2l.5 1h-1zM221 53.3v1.3h1.2l-1.2 1.3-1.3-1.3h1.3"/>
<path d="M221.5 42.4h1v6.6h-1M222 47.5h1M222 42.9h1M222.5 42.9l.5 1h-1zM222.5 47.5l.5 1h-1zM200.7 185.4v1.3h1.2l-1.2 1.3-1.3-1.3h1.3M20.3 209.6l.8 1.2M20.3 209.6l-.7 1.2M20.3 209.6v2.5M130.8 251.5v1.2h-1.3l1.3 1.3 1.3-1.3h-1.3"/>
</g>
<path d="M218.4 41.7h5.1v8.1h-5.1z" fill="none" stroke="#840000" stroke-width=".25"/>
<g fill="none" stroke="#000" stroke-width=".18">
<path d="M221 27.9h.1M221 39.4v2.5M215.9 44.5h2.5M215.9 47h2.5M221 53.3h.1M221 49.5v2.6M223.5 44.5h2.6M223.5 47h2.6M190.5 175.3v.7M190.5 179.6v.7M200.7 185.4h.1M20.3 212.1h.1"/>
<path d="M20.3 218.4v.8M20.3 222.8v.7M130.8 251.5h.1"/>
</g>
<path d="M189.7 176h1.6v3.6h-1.6zM19.6 219.2h1.5v3.6h-1.5z" fill="none" stroke="#840000" stroke-width=".2"/>
<path d="M367 60.3h7.6v6.4h-7.6z" fill="#ffffc2"/>
<g fill="none" stroke="#840000" stroke-width=".18">
<path d="M373.1 61.9l-2 3.1M283.2 129.5v1.3h1.3l-1.3 1.3-1.3-1.3h1.3M290.8 129.5v1.3h1.3l-1.3 1.3-1.2-1.3h1.2"/>
<circle cx="368.3" cy="61.5" r=".51"/>
<circle cx="370.8" cy="65.5" r=".51"/>
<circle cx="373.4" cy="61.5" r=".51"/>
</g>
<path d="M367 60.3h7.6v6.4h-7.6z" fill="none" stroke="#840000" stroke-width=".25"/>
<path d="M368.3 58.4v2.6M373.4 58.4v2.6M370.8 66v2.6M283.2 129.5h.1M290.8 129.5h.1M290.8 123.2v2M290.8 126.2v2.1" fill="none" stroke="#000" stroke-width=".18"/>
<path d="M289.3 125.2h3.1" fill="none" stroke="#840000" stroke-width=".3"/>
<path d="M289.3 126.2h3.1" fill="none" stroke="#840000" stroke-width=".33"/>
<path d="M369.6 139.7h15.2v20.3h-15.2z" fill="#ffffc2"/>
<path d="M369.6 139.7h15.2v20.3h-15.2z" fill="none" stroke="#840000" stroke-width=".25"/>
<g fill="none" stroke="#000" stroke-width=".18">
<path d="M325.1 53.3h.1M311.1 78.7v.8M313.7 78.7v.8M370.8 69.9h.1M256.5 96.5h.1M264.2 96.5h.1M311.1 83.1v.7M313.7 83.1v.7M283.2 123.2v2M283.2 126.2v2.1M367 142.2h2.6M367 144.8h2.6"/>
<path d="M367 149.9h2.6M367 152.4h2.6M384.8 142.2h2.5M384.8 152.4h2.5M384.8 147.3h2.5M377.2 160v2.6M190.5 185.4h.1M20.3 234.9v2.1M20.3 238v2M35.6 232.4v2.5M20.3 245.1h.1M35.6 245.1h.1"/>
<path d="M35.6 240v2.6"/>
</g>
<g fill="none" stroke="#840000" stroke-width=".18">
<path d="M325.1 53.3v1.3h1.3l-1.3 1.3-1.3-1.3h1.3M370.8 69.9v1.2h-1.2l1.2 1.3 1.3-1.3h-1.3M256.5 96.5v1.3h1.3l-1.3 1.3-1.2-1.3h1.2M264.2 96.5v1.3h1.2l-1.2 1.3-1.3-1.3h1.3M190.5 185.4v1.3h1.3l-1.3 1.3-1.3-1.3h1.3M32.5 237.5h1.8M34.3 234.9v5.1M20.3 245.1v1.3h1.3l-1.3 1.2-1.3-1.2h1.3M35.6 245.1v1.3h1.2l-1.2 1.2-1.3-1.2h1.3"/>
<circle cx="35.6" cy="235.5" r=".51"/>
<circle cx="35.6" cy="239.5" r=".51"/>
</g>
<path d="M310.4 79.5h1.5v3.6h-1.5zM312.9 79.5h1.6v3.6h-1.6z" fill="none" stroke="#840000" stroke-width=".2"/>
<path d="M281.7 125.2h3M18.8 237h3" fill="none" stroke="#840000" stroke-width=".3"/>
<path d="M281.7 126.2h3M18.8 238h3" fill="none" stroke="#840000" stroke-width=".33"/>
<path d="M256.5 139.7h61v48.3h-61z" fill="#ffffc2"/>
<path d="M256.5 139.7h61v48.3h-61z" fill="none" stroke="#840000" stroke-width=".25"/>
<path d="M22.9 43.2h.1M38.1 43.2h.1M63.5 109.2h.1M257.7 142.5h5.2M94 210.8h.1M64.8 252.7h.1M64.8 254v.8M64.8 258.3v.8" fill="none" stroke="#000" stroke-width=".18"/>
<path d="M64 254.8h1.5v3.5h-1.5z" fill="none" stroke="#840000" stroke-width=".2"/>
<path d="M22.9 43.2v1.3h1.2l-1.2 1.2-1.3-1.2h1.3M38.1 43.2v1.3h1.3l-1.3 1.2-1.3-1.2h1.3M63.5 109.2v1.3h1.3l-1.3 1.3-1.3-1.3h1.3M94 208.3l.7 1.3M94 208.3l-.8 1.3M94 208.3v2.5M64.8 250.2l.7 1.3M64.8 250.2l-.8 1.3M64.8 250.2v2.5" fill="none" stroke="#840000" stroke-width=".18"/>
<path d="M119.4 264.2h7.6v2.5h-7.6z" fill="#ffffc2"/>
<path d="M119.4 264.2h7.6v2.5h-7.6z" fill="none" stroke="#840000" stroke-width=".25"/>
<path d="M120.5 264.2h.3v1.2h-.3zM123.1 264.2h.2v1.2h-.2zM125.6 264.2h.3v1.2h-.3z" fill="none" stroke="#840000" stroke-width=".18"/>
<path d="M120.6 260.3v3.9M123.2 260.3v3.9M125.7 260.3v3.9" fill="none" stroke="#000" stroke-width=".18"/>
<path d="M22.9 66h2.5v7.7h-2.5z" fill="#ffffc2"/>
<path d="M22.9 66h2.5v7.7h-2.5z" fill="none" stroke="#840000" stroke-width=".25"/>
<path d="M24.1 72.3h1.3v.2h-1.3zM24.1 69.7h1.3v.3h-1.3zM24.1 67.2h1.3v.2h-1.3zM64.8 270.5v1.3h1.2l-1.2 1.2-1.3-1.2h1.3M88.9 264.2v1.2h1.3l-1.3 1.3-1.3-1.3h1.3" fill="none" stroke="#840000" stroke-width=".18"/>
<path d="M25.4 72.4h3.8M25.4 69.9h3.8M25.4 67.3h3.8M64.8 270.5h.1M88.9 264.2h.1" fill="none" stroke="#000" stroke-width=".18"/>
<path d="M20.3 80h20.3v25.4h-20.3z" fill="#ffffc2"/>
<path d="M20.3 80h20.3v25.4h-20.3z" fill="none" stroke="#840000" stroke-width=".25"/>
<path d="M30.2 80h.5v1h-.5zM39.6 89.9h1v.5h-1zM39.6 92.5h1v.5h-1zM39.6 95h1v.5h-1zM39.6 97.5h1v.5h-1zM27.7 104.4h.5v1h-.5zM30.2 104.4h.5v1h-.5z" fill="none" stroke="#840000" stroke-width=".18"/>
<path d="M30.5 77.5v2.5M34.3 84.1h5.2M40.6 90.2h2.6M40.6 92.7h2.6M40.6 95.3h2.6M40.6 97.8h2.6M27.9 105.4v2.6M30.5 105.4v2.6" fill="none" stroke="#000" stroke-width=".18"/>
<path d="M18.4 66h3.8v5.1h-3.8z" fill="#ffffc2"/>
<path d="M22.9 40.6l1-.6-1-.6-1.1 .6 1.1 .6v1.3M22.2 67.3h-2.5a1.8 1.8 0 0 0 0 2.6h2.5M63.5 101.6v2.5M69.8 109.2v1.3h-1.2l1.2 1.3 1.3-1.3h-1.3" fill="none" stroke="#840000" stroke-width=".18"/>
<path d="M18.4 66h3.8v5.1h-3.8zM63.5 101.6l1.3 2.5h-2.6zM64.8 101.6h-2.6v.5" fill="none" stroke="#840000" stroke-width=".25"/>
<g fill="#840000" stroke="#840000" stroke-width=".18">
<circle cx="19.7" cy="67.3" r=".25"/>
<circle cx="19.7" cy="69.8" r=".25"/>
</g>
<path d="M22.9 41.9h.1M63.5 99.1v2.5M63.5 104.1v2.6M69.8 109.2h.1M64.8 264.2v2M64.8 267.2v2" fill="none" stroke="#000" stroke-width=".18"/>
<path d="M104.4 140a1.02 1.02 0 0 1 1 1 1.02 1.02 0 0 1-1 1zM103.2 140.3l.7-.3v2a1.02 1.02 0 0 1-.9-.6 1.02 1.02 0 0 1 .2-1.1z" fill="none" stroke="#9c9b98" stroke-width=".18"/>
<g fill="#9c9b98" stroke="#9c9b98" stroke-width=".18">
<path d="M103.2 140.3l.7-.3v2a1.02 1.02 0 0 1-.9-.6 1.02 1.02 0 0 1 .2-1.1z"/>
<path d="M104.4 140a1.02 1.02 0 0 1 1 1 1.02 1.02 0 0 1-1 1z"/>
</g>
<path d="M100.3 141h2.6M105.4 141h2.5" fill="none" stroke="#7a7a77" stroke-width=".18"/>
<path d="M101.1 139.4l6.1 3.1M107.2 139.4l-6.1 3.1" fill="none" stroke="#e12e31" stroke-width=".46"/>
<path d="M63.2 266.2h3.1" fill="none" stroke="#840000" stroke-width=".3"/>
<path d="M63.2 267.2h3.1" fill="none" stroke="#840000" stroke-width=".33"/>
<path d="M96.5 74.9h15.3v30.5h-15.3z" fill="#ffffc2"/>
<path d="M96.5 74.9h15.3v30.5h-15.3zM180.3 176.5h2.6l-1.3 2.6zM180.3 179.1h2.6" fill="none" stroke="#840000" stroke-width=".25"/>
<g fill="none" stroke="#840000" stroke-width=".18">
<path d="M69.8 58.4l1.1-.6-1.1-.6-1 .6 1 .6v1.3M101.1 82.7v1h1.8M101.1 87.8v1h1.8M101.1 92.8v1.1h1.8M101.1 97.9v1h1.8M102.9 82.7l1.7 1-1.7 1zM102.9 87.8l1.7 1-1.7 1zM102.9 92.8l1.7 1.1-1.7 1zM102.9 97.9l1.7 1-1.7 1zM102.9 81.7l1.7-1.1v2.1zM102.9 81.7h-1.8v1h-1.3M102.9 86.7l1.7-1v2.1z"/>
<path d="M102.9 86.7h-1.8v1.1h-1.3M102.9 91.8l1.7-1v2zM102.9 91.8h-1.8v1h-1.3M102.9 96.9l1.7-1v2zM102.9 96.9h-1.8v1h-1.3M104.6 81.7h1.8v1M104.6 86.7h1.8v1.1M104.6 91.8h1.8v1M104.6 96.9h1.8v1M108.2 87.8h-1.8v1h-1.8M108.2 92.8h-1.8v1.1h-1.8M108.2 97.9h-1.8v1h-1.8"/>
<path d="M108.5 82.7h-2.1v1h-1.8M30.5 109.2v1.3h1.2l-1.2 1.3-1.3-1.3h1.3M104.1 110.5v1.3h-1.2l1.2 1.2 1.3-1.2h-1.3M180.8 179.6l-1.5 1.5v-.8v.8h.8M181.6 176.5v2.6M180.8 180.8l-1.5 1.6v-.8v.8h.8M181.6 185.4v1.3h1.3l-1.3 1.3-1.3-1.3h1.3M83.8 219.7v1.3h-1.3l1.3 1.2 1.3-1.2h-1.3M94 219.7v1.3h-1.3l1.3 1.2 1.2-1.2h-1.2"/>
</g>
<g fill="none" stroke="#000" stroke-width=".18">
<path d="M69.8 59.7h.1M106.7 72.4v2.5M94 87.6h2.5M94 92.7h2.5M94 97.8h2.5M111.8 82.6h2.5M111.8 87.6h2.5M111.8 92.7h2.5M111.8 97.8h2.5M30.5 109.2h.1M104.1 110.5h.1M104.1 105.4v2.6"/>
<path d="M181.6 174v2.5M181.6 179.1v2.5M184.1 170.2h.8M188.5 170.2h.7M181.6 185.4h.1M205.7 189.2h2.1M208.8 189.2h2M83.8 219.7h.1M94 219.7h.1"/>
</g>
<path d="M103.2 137.7l.7-.3v2a1.02 1.02 0 0 1-.9-.6 1.02 1.02 0 0 1 .2-1.1zM103.2 126.3l.7-.3v2a1.02 1.02 0 0 1-.9-.6 1.02 1.02 0 0 1 .2-1.1zM104.4 137.4a1.02 1.02 0 0 1 1 1 1.02 1.02 0 0 1-1 1zM104.4 126a1.02 1.02 0 0 1 1 1 1.02 1.02 0 0 1-1 1z" fill="none" stroke="#9c9b98" stroke-width=".18"/>
<g fill="#9c9b98" stroke="#9c9b98" stroke-width=".18">
<path d="M103.2 137.7l.7-.3v2a1.02 1.02 0 0 1-.9-.6 1.02 1.02 0 0 1 .2-1.1z"/>
<path d="M104.4 137.4a1.02 1.02 0 0 1 1 1 1.02 1.02 0 0 1-1 1z"/>
<path d="M103.2 126.3l.7-.3v2a1.02 1.02 0 0 1-.9-.6 1.02 1.02 0 0 1 .2-1.1z"/>
<path d="M104.4 126a1.02 1.02 0 0 1 1 1 1.02 1.02 0 0 1-1 1z"/>
</g>
<path d="M100.3 138.4h2.6M100.3 127h2.6M105.4 138.4h2.5M105.4 127h2.5" fill="none" stroke="#7a7a77" stroke-width=".18"/>
<path d="M101.1 136.9l6.1 3.1M101.1 125.5l6.1 3M107.2 136.9l-6.1 3.1M107.2 125.5l-6.1 3" fill="none" stroke="#e12e31" stroke-width=".46"/>
<path d="M184.9 169.4h3.6v1.5h-3.6z" fill="none" stroke="#840000" stroke-width=".2"/>
<path d="M207.8 187.7v3.1" fill="none" stroke="#840000" stroke-width=".3"/>
<path d="M208.8 187.7v3.1" fill="none" stroke="#840000" stroke-width=".33"/>
<path d="M74.9 229.9h28v27.9h-28z" fill="#ffffc2"/>
<path d="M74.9 229.9h28v27.9h-28z" fill="none" stroke="#840000" stroke-width=".25"/>
<g fill="none" stroke="#000" stroke-width=".18">
<path d="M34.3 59.7h.1M40.6 59.7h.1M109.2 59.7h.1M125.7 59.7h.1M109.2 68.6h.1M125.7 76.2h.1M125.7 62.2v.8M125.7 66.5v.8M207 78.7v.8M207 83.1v.7M247.6 138.4h.1M247.6 120.7h.1"/>
<path d="M247.6 121.9v.8M247.6 126.2v.8M247.6 132.1v2M247.6 135.1v2.1M219.7 158.8v.7M226.1 154.9h.1M231.1 158.8v.7M219.7 163.1v.7M231.1 163.1v.7M377.2 163.8h.1M228.6 190.5h.1M69.8 210.8h.1"/>
<path d="M83.8 210.8h.1M83.8 213.4v2M83.8 216.4v2M94 213.4v2M94 216.4v2M71.1 233.7h3.8M86.4 226.1v3.8M91.4 226.1v3.8M99.3 237.7h2.9M102.9 233.7h3.8M102.9 236.2h3.8M102.9 238.8h3.8"/>
<path d="M71.1 241.3h3.8M71.1 243.8h3.8M71.1 248.9h3.8M75.6 247.9h5.1M86.4 257.8v3.8M88.9 257.8v3.8M91.4 257.8v3.8M99.2 240.3h3M102.9 241.3h3.8M102.9 248.9h3.8M102.9 246.4h3.8M102.9 251.5h3.8"/>
<path d="M102.9 254h3.8"/>
</g>
<path d="M246.1 134.1h3.1M82.3 215.4h3M92.5 215.4h3" fill="none" stroke="#840000" stroke-width=".3"/>
<path d="M246.1 135.1h3.1M82.3 216.4h3M92.5 216.4h3" fill="none" stroke="#840000" stroke-width=".33"/>
<g fill="none" stroke="#840000" stroke-width=".18">
<path d="M34.3 57.2l.8 1.2M34.3 57.2l-.8 1.2M34.3 57.2v2.5M40.6 57.2l-.7 1.2M40.6 57.2l.8 1.2M40.6 57.2v2.5M109.2 57.2l.8 1.2M109.2 57.2l-.7 1.2M109.2 57.2v2.5M125.7 57.2l.8 1.2M125.7 57.2l-.7 1.2M125.7 57.2v2.5"/>
<path d="M109.2 68.6v1.3h-1.3l1.3 1.2 1.3-1.2h-1.3M125.7 76.2v1.3h-1.2l1.2 1.2 1.3-1.2h-1.3M247.6 118.1l.8 1.3M247.6 118.1l-.7 1.3M247.6 118.1v2.6M247.6 138.4v1.3h1.3l-1.3 1.3-1.2-1.3h1.2M226.1 152.4l.7 1.3M226.1 152.4l-.8 1.3M226.1 152.4v2.5M377.2 163.8v1.3h1.3l-1.3 1.3-1.3-1.3h1.3M228.6 190.5v1.3h1.3l-1.3 1.2-1.3-1.2h1.3M69.8 208.3l.8 1.3"/>
<path d="M69.8 208.3l-.7 1.3M69.8 208.3v2.5M83.8 208.3l.8 1.3M83.8 208.3l-.7 1.3M83.8 208.3v2.5"/>
</g>
<path d="M125 63h1.5v3.5h-1.5zM206.2 79.5h1.6v3.6h-1.6zM246.9 122.7h1.5v3.5h-1.5zM218.9 159.5h1.6v3.6h-1.6zM230.4 159.5h1.5v3.6h-1.5z" fill="none" stroke="#840000" stroke-width=".2"/>
<path d="M125 70.6h1.5v3.6h-1.5z" fill="none" stroke="#9c9b98" stroke-width=".2"/>
<path d="M125.7 69.9v.7M125.7 74.2v.7" fill="none" stroke="#7a7a77" stroke-width=".18"/>
<path d="M124.6 69.9l2.3 5M126.9 69.9l-2.3 5" fill="none" stroke="#e12e31" stroke-width=".46"/>
<path d="M67.3 87.4h5.1v8.1h-5.1z" fill="#ffffc2"/>
<g fill="#840000" stroke="#840000" stroke-width=".18">
<path d="M368.3 29.5l.4 1h-.8z"/>
<circle cx="71.4" cy="90.2" r=".25"/>
<circle cx="70.4" cy="88.1" r=".25"/>
<circle cx="70.4" cy="94.7" r=".25"/>
<circle cx="69.3" cy="88.1" r=".25"/>
<circle cx="69.3" cy="94.7" r=".25"/>
<circle cx="68.3" cy="92.7" r=".25"/>
<circle cx="366.5" cy="29.2" r=".25"/>
<circle cx="370.1" cy="29.2" r=".25"/>
</g>
<g fill="none" stroke="#840000" stroke-width=".18">
<path d="M365.8 29.2h.7M366.5 31v-2.6h3.6v2.6M368 28.1l.7 .3-.7 .4zM368.3 31.5v2.8M368.6 27.9l.1 .2v.7l.1 .2M370.8 29.2h-2.5v1.8M67.3 90.2h5.1M67.3 92.7h5.1M67.8 93.2h1M67.8 88.6h1M68.3 88.6l.5 1.1h-1zM68.3 93.2l.5 1h-1z"/>
<path d="M69.3 90.9h1.1v.4M69.3 88.1h-1v6.6h1M69.8 87.6l.6 .5h-1.1l.5 .5v5.6l.6 .5h-1.1l.5 .6M69.8 90.9l.6 1h-1.1zM70.4 88.1h1v6.6h-1M70.9 93.2h1M70.9 88.6h1M71.4 88.6l.5 1.1h-1zM71.4 93.2l.5 1h-1zM172.7 96.5v1.3h1.3l-1.3 1.3-1.3-1.3h1.3M180.3 96.5v1.3h1.3l-1.3 1.3-1.2-1.3h1.2"/>
</g>
<g fill="none" stroke="#840000" stroke-width=".25">
<path d="M366 31h1M366.4 31.5h3.8M367.8 31h1M369.6 31h1M67.3 87.4h5.1v8.1h-5.1z"/>
<circle cx="368.3" cy="30.1" r="2.79"/>
</g>
<g fill="none" stroke="#000" stroke-width=".18">
<path d="M363.2 29.2h2.6M368.3 34.3v2.5M370.8 39.4h.8M370.8 29.2h2.6M375.2 39.4h.7M379.7 50.8h.8M384 50.8h.8M50.8 90.2h.8M55.1 90.2h.8M64.8 90.2h2.5M64.8 92.7h2.5M69.8 85.1v2.5"/>
<path d="M69.8 95.3v2.5M72.4 90.2h2.5M72.4 92.7h2.5M172.7 96.5h.1M180.3 96.5h.1M392.4 129.5v2.1M392.4 132.6v2"/>
</g>
<path d="M371.6 38.6h3.6v1.5h-3.6zM380.5 50h3.5v1.6h-3.5zM51.6 89.4h3.5v1.5h-3.5z" fill="none" stroke="#840000" stroke-width=".2"/>
<path d="M390.9 131.6h3.1" fill="none" stroke="#840000" stroke-width=".3"/>
<path d="M390.9 132.6h3.1" fill="none" stroke="#840000" stroke-width=".33"/>
<path d="M351.8 36.8h5.1v2.6h-5.1z" fill="#ebeae8"/>
<path d="M351.8 36.8h5.1v2.6h-5.1z" fill="none" stroke="#9c9b98" stroke-width=".25"/>
<path d="M352.9 36.8h.3v1.3h-.3zM355.5 36.8h.2v1.3h-.2z" fill="none" stroke="#9c9b98" stroke-width=".18"/>
<path d="M353.1 33v3.8M355.6 33v3.8" fill="none" stroke="#7a7a77" stroke-width=".18"/>
<path d="M350.4 34.3l7.8 7.6M358.2 34.3l-7.8 7.6" fill="none" stroke="#e12e31" stroke-width=".46"/>
<path d="M127 25.4l-.8 1.3M127 25.4l.8 1.3M127 25.4v2.5M106.7 43.2v1.3h1.2l-1.2 1.2-1.3-1.2h1.3M116.8 43.2v1.3h1.3l-1.3 1.2-1.2-1.2h1.2M127 43.2v1.3h1.3l-1.3 1.2-1.3-1.2h1.3M232.7 181.6h-1.3v5.1h1.3M234.9 181.6v.5M234.9 186.2v.5M237.2 181.6h1.3v5.1h-1.3" fill="none" stroke="#840000" stroke-width=".18"/>
<path d="M233.7 182.1h2.5M233.7 186.2h2.5" fill="none" stroke="#840000" stroke-width=".51"/>
<path d="M105.2 36.3h3M115.3 36.3h3.1M125.5 36.3h3M232.4 183h5.1v2.3h-5.1z" fill="none" stroke="#840000" stroke-width=".3"/>
<path d="M106.7 34.3v2M106.7 37.3v2.1M116.8 34.3v2M116.8 37.3v2.1M127 27.9h.1M127 34.3v2M127 37.3v2.1M106.7 43.2h.1M116.8 43.2h.1M127 43.2h.1" fill="none" stroke="#000" stroke-width=".18"/>
<path d="M105.2 37.3h3M115.3 37.3h3.1M125.5 37.3h3" fill="none" stroke="#840000" stroke-width=".33"/>
<path d="M170.2 26.7h20.3v63.5h-20.3z" fill="#ffffc2"/>
<g fill="none" stroke="#840000" stroke-width=".18">
<path d="M189.5 29h1v.5h-1zM189.5 34h1v.5h-1zM189.5 36.6h1v.5h-1zM91.4 43.2v1.3h1.3l-1.3 1.2-1.2-1.2h1.2M189.5 41.7h1v.5h-1zM189.5 44.2h1v.5h-1zM189.5 46.7h1v.5h-1zM189.5 49.3h1v.5h-1zM189.5 54.4h1v.5h-1zM189.5 56.9h1v.5h-1zM189.5 62h1v.5h-1zM189.5 64.5h1v.5h-1z"/>
<path d="M189.5 69.6h1v.5h-1zM189.5 72.1h1v.5h-1zM189.5 77.2h1v.5h-1zM189.5 79.8h1v.5h-1zM180.1 89.2h.5v1h-.5zM189.5 84.8h1v.5h-1zM189.5 87.4h1v.5h-1zM208.3 96.5v1.3h1.2l-1.2 1.3-1.3-1.3h1.3"/>
</g>
<path d="M170.2 26.7h20.3v63.5h-20.3zM172.7 50.8a.64 .64 0 0 1 .7-.6 .64 .64 0 0 1 .6 .6M172.7 58.4a.64 .64 0 0 0 .7 .7 .64 .64 0 0 0 .6-.7" fill="none" stroke="#840000" stroke-width=".25"/>
<path d="M172 49.5a1.9 1.9 0 0 1 2.1-.5 1.9 1.9 0 0 1 1.2 1.8v7.6a1.91 1.91 0 0 1-1.9 1.9 1.91 1.91 0 0 1-2-1.9l.1-7.7 .1-.7zM177.8 54.1v1.3l2.5 2.5M180.3 50.3v10.2M182.9 52.8v1.3l-2.6 2.5" fill="none" stroke="#840000" stroke-width=".51"/>
<g fill="#840000" stroke="#840000" stroke-width=".25">
<path d="M172.7 50.8h1.3v7.6h-1.3z"/>
<path d="M172.9 50.4a.64 .64 0 0 1 .7-.2 .64 .64 0 0 1 .4 .6h-1.3z"/>
<path d="M172.7 58.4h1.3a.64 .64 0 0 1-.6 .7 .64 .64 0 0 1-.7-.7z"/>
<path d="M180.3 47.8l1.3 2.5h-2.5z"/>
<path d="M182.2 51.6h1.3v1.2h-1.3z"/>
<circle cx="177.8" cy="53.5" r=".63"/>
</g>
<circle cx="180.3" cy="60.5" r="1.27" fill="#840000" stroke="#840000" stroke-width=".18"/>
<g fill="none" stroke="#000" stroke-width=".18">
<path d="M190.5 29.2h5.1M190.5 34.3h5.1M190.5 36.8h5.1M91.4 43.2h.1M190.5 41.9h5.1M190.5 44.5h5.1M190.5 47h5.1M190.5 49.5h5.1M190.5 54.6h5.1M190.5 57.2h5.1M190.5 62.2h5.1M190.5 64.8h5.1"/>
<path d="M190.5 69.9h5.1M190.5 72.4h5.1M190.5 77.5h5.1M172.7 90.2v5.1M180.3 90.2v5.1M190.5 80h5.1M190.5 85.1h5.1M190.5 87.6h5.1M208.3 96.5h.1"/>
</g>
<path d="M86.4 27.3h10.1v9.5h-10.1z" fill="#ffffc2"/>
<path d="M86.4 27.3h10.1v9.5h-10.1z" fill="none" stroke="#840000" stroke-width=".25"/>
<g fill="none" stroke="#000" stroke-width=".18">
<path d="M83.8 29.2h2.6M83.8 31.8h2.6M91.4 36.8v2.6M96.5 29.2h2.6M96.5 31.8h2.6M87.6 68.6h.1M87.6 62.2v2.1M87.6 65.3v2M109.2 62.2v2.1M109.2 65.3v2M241.3 190.5h.1M252.7 193h.1"/>
<path d="M287 193h.1M321.3 193h.1M321.3 185.4v2.1M321.3 188.5v2"/>
</g>
<path d="M87.6 68.6v1.3h-1.2l1.2 1.2 1.3-1.2h-1.3M241.3 190.5v1.3h1.3l-1.3 1.2-1.3-1.2h1.3M252.7 193v1.3h1.3l-1.3 1.3-1.2-1.3h1.2M287 193v1.3h1.3l-1.3 1.3-1.3-1.3h1.3M321.3 193v1.3h-1.3l1.3 1.3 1.3-1.3h-1.3" fill="none" stroke="#840000" stroke-width=".18"/>
<path d="M86.1 64.3h3.1M107.7 64.3h3M319.8 187.5h3" fill="none" stroke="#840000" stroke-width=".3"/>
<path d="M86.1 65.3h3.1M107.7 65.3h3M319.8 188.5h3" fill="none" stroke="#840000" stroke-width=".33"/>
<path d="M254 26.7h20.3v63.5h-20.3z" fill="#ffffc2"/>
<g fill="none" stroke="#840000" stroke-width=".18">
<path d="M273.3 29h1v.5h-1zM273.3 34h1v.5h-1zM273.3 36.6h1v.5h-1zM273.3 41.7h1v.5h-1zM273.3 44.2h1v.5h-1zM273.3 46.7h1v.5h-1zM273.3 49.3h1v.5h-1zM273.3 54.4h1v.5h-1zM273.3 56.9h1v.5h-1zM273.3 62h1v.5h-1zM273.3 64.5h1v.5h-1zM273.3 69.6h1v.5h-1z"/>
<path d="M273.3 72.1h1v.5h-1zM273.3 77.2h1v.5h-1zM273.3 79.8h1v.5h-1zM263.9 89.2h.5v1h-.5zM273.3 84.8h1v.5h-1zM273.3 87.4h1v.5h-1zM363.2 163.8v1.3h1.3l-1.3 1.3-1.3-1.3h1.3"/>
</g>
<path d="M254 26.7h20.3v63.5h-20.3zM256.5 50.8a.64 .64 0 0 1 .7-.6 .64 .64 0 0 1 .6 .6M256.5 58.4a.64 .64 0 0 0 .7 .7 .64 .64 0 0 0 .6-.7" fill="none" stroke="#840000" stroke-width=".25"/>
<path d="M255.8 49.5a1.91 1.91 0 0 1 2.1-.5 1.91 1.91 0 0 1 1.2 1.8v7.6a1.91 1.91 0 0 1-1.9 1.9 1.91 1.91 0 0 1-1.9-1.9v-7.7l.1-.7zM261.6 54.1v1.3l2.6 2.5M264.2 50.3v10.2M266.7 52.8v1.3l-2.5 2.5" fill="none" stroke="#840000" stroke-width=".51"/>
<g fill="#840000" stroke="#840000" stroke-width=".25">
<path d="M256.5 50.8h1.3v7.6h-1.3z"/>
<path d="M256.7 50.4a.64 .64 0 0 1 .7-.2 .64 .64 0 0 1 .4 .6h-1.3z"/>
<path d="M256.5 58.4h1.3a.64 .64 0 0 1-.6 .7 .64 .64 0 0 1-.7-.7z"/>
<path d="M264.2 47.8l1.2 2.5h-2.5z"/>
<path d="M266.1 51.6h1.2v1.2h-1.2z"/>
<circle cx="261.6" cy="53.5" r=".63"/>
</g>
<circle cx="264.2" cy="60.5" r="1.27" fill="#840000" stroke="#840000" stroke-width=".18"/>
<g fill="none" stroke="#000" stroke-width=".18">
<path d="M274.3 29.2h5.1M274.3 34.3h5.1M274.3 36.8h5.1M274.3 41.9h5.1M274.3 44.5h5.1M274.3 47h5.1M274.3 49.5h5.1M274.3 54.6h5.1M274.3 57.2h5.1M209.5 78.7v.8M274.3 62.2h5.1M274.3 64.8h5.1"/>
<path d="M274.3 69.9h5.1M274.3 72.4h5.1M274.3 77.5h5.1M209.5 83.1v.7M256.5 90.2v5.1M264.2 90.2v5.1M274.3 80h5.1M274.3 85.1h5.1M274.3 87.6h5.1M363.2 152.4v.8M363.2 156.7v.8M363.2 163.8h.1"/>
</g>
<path d="M208.8 79.5h1.5v3.6h-1.5zM362.5 153.2h1.5v3.5h-1.5z" fill="none" stroke="#840000" stroke-width=".2"/>
<path d="M322.6 41.7h5.1v8.1h-5.1z" fill="#ffffc2"/>
<g fill="#840000" stroke="#840000" stroke-width=".18">
<circle cx="326.6" cy="44.4" r=".25"/>
<circle cx="325.6" cy="42.4" r=".25"/>
<circle cx="325.6" cy="49" r=".25"/>
<circle cx="324.6" cy="42.4" r=".25"/>
<circle cx="324.6" cy="49" r=".25"/>
<circle cx="323.6" cy="47" r=".25"/>
</g>
<g fill="none" stroke="#840000" stroke-width=".18">
<path d="M327.5 36.8h6.9v2.6h-6.9l-1.1-1.3zM286.9 53.3h6.3v2.6h-6.3l-1.2-1.3zM322.6 44.5h5.1M322.6 47h5.1M323.1 47.5h1M323.1 42.9h1M323.6 42.9l.5 1h-1zM323.6 47.5l.5 1h-1zM324.6 45.2h1v.4M324.6 42.4h-1v6.6h1M325.1 41.9l.5 .5h-1l.5 .5v5.6l.5 .5h-1l.5 .5M325.1 45.2l.5 1h-1z"/>
<path d="M325.6 42.4h1v6.6h-1M326.1 47.5h1.1M326.1 42.9h1.1M326.6 42.9l.6 1h-1.1zM326.6 47.5l.6 1h-1.1zM371.6 51.6l-1.5 1.5h.7h-.7v-.8M372.9 51.6l-1.6 1.5h.8h-.8v-.8M373.4 50.8h2.5M63.5 77.5v2.5M127 86.4h10l1.1 1.2-1.1 1.3h-10zM380.7 127h5.5l1.1 1.3-1.1 1.2h-5.5zM392.4 135.9v1.3h1.3l-1.3 1.2-1.2-1.2h1.2"/>
<path d="M356.5 141h6.9l1.1 1.2-1.1 1.3h-6.9zM388.6 146h6.9l1.2 1.3-1.2 1.3h-6.9zM209 165.1h6.9v2.5h-6.9l-1.1-1.2zM36.8 226.1h8.3l1.1 1.2-1.1 1.3h-8.3z"/>
</g>
<path d="M322.6 41.7h5.1v8.1h-5.1zM373.4 50.8l2.5-1.3v2.6zM373.4 49.5v2.6M63.5 77.5l1.3 2.5h-2.6zM64.8 77.5h-2.6v.5" fill="none" stroke="#840000" stroke-width=".25"/>
<g fill="none" stroke="#000" stroke-width=".18">
<path d="M325.1 39.4v2.5M351.8 29.2h.8M356.1 29.2h.8M320 44.5h2.6M320 47h2.6M325.1 49.5v2.6M327.7 44.5h2.5M327.7 47h2.5M370.8 50.8h2.6M375.9 50.8h2.6M63.5 74.9v2.6M50.8 92.7h.8"/>
<path d="M55.1 92.7h.8M63.5 80v2.6M392.4 135.9h.1M331.5 185.4v2.1M331.5 188.5v2M341.6 185.4v.8M341.6 189.7v.8"/>
</g>
<path d="M352.6 28.4h3.5v1.6h-3.5zM51.6 91.9h3.5v1.6h-3.5zM340.9 186.2h1.5v3.5h-1.5z" fill="none" stroke="#840000" stroke-width=".2"/>
<path d="M329.9 187.5h3.1" fill="none" stroke="#840000" stroke-width=".3"/>
<path d="M329.9 188.5h3.1" fill="none" stroke="#840000" stroke-width=".33"/>
<path d="M229.7 45.7h9.6l1.1 1.3-1.1 1.3h-9.6l-1.1-1.3zM322.4 157.5h12.4l1.1 1.3-1.1 1.2h-12.4l-1.1-1.2zM322.4 147.3h12.4l1.1 1.3-1.1 1.3h-12.4l-1.1-1.3zM322.4 154.9h12.4l1.1 1.3-1.1 1.3h-12.4l-1.1-1.3zM322.4 144.8h12.4l1.1 1.3-1.1 1.2h-12.4l-1.1-1.2z" fill="none" stroke="#ffa049" stroke-width=".18"/>
<path d="M286.9 76.2h8.9l1.1 1.3-1.1 1.2h-8.9l-1.2-1.2zM286.9 63.5h10.5v2.5h-10.5l-1.2-1.2zM127 91.4h10.6l1.1 1.3-1.1 1.3h-10.6zM128.1 96.5h9l1.1 1.3-1.1 1.3h-9l-1.1-1.3z" fill="none" stroke="#008484" stroke-width=".18"/>
<g fill="#840000">
<path d="M19.2 28.7h.5l-.1 .1 .3 .8 .3-.8-.1-.1h.4l-.6 1.2z"/>
<path d="M20.5 29.4h.6v.2l-.1 .1 .2 .1a.23 .23 0 0 1-.1 .3 .23 .23 0 0 1-.2 0h-.4l.1-.3h.1v.3a.2 .2 0 0 0 .3-.1 .2 .2 0 0 0 0-.2 .2 .2 0 0 0-.3 0h-.1v-.4h.1v.3a.19 .19 0 0 0 .3 0 .19 .19 0 0 0 0-.3 .19 .19 0 0 0-.3 0z"/>
<path d="M21.3 29.4h.3l-.1 .5 .2 .2 .2-.2-.1-.5h.3l-.2 .4a.3 .3 0 0 1-.3 .3 .3 .3 0 0 1-.2-.3z"/>
<path d="M22.2 29.4l.4-.1v.3l-.2-.2-.2 .1 .1 .1a.28 .28 0 0 1 .3 .3 .28 .28 0 0 1-.4 .2v-.2a.18 .18 0 0 0 .1 .2 .18 .18 0 0 0 .2-.3l-.3-.2z"/>
</g>
<path d="M17.5 27.9h5.5l1.1 1.3-1.1 1.3h-5.5zM74.6 27.9h5.6l1.1 1.3-1.1 1.3h-5.6zM389.7 27.9h7v2.6h-7l-1.1-1.3zM285.7 55.9h6.7l1.1 1.3-1.1 1.2h-6.7zM75.8 81.3h8.2l1.1 1.3-1.1 1.2h-8.2zM286.9 85.1h9.9v2.5h-9.9l-1.2-1.2zM127 232.4h6.3l1.2 1.3-1.2 1.3h-6.3zM128.1 234.9h6.7v2.6h-6.7l-1.1-1.3z" fill="none" stroke="#840000" stroke-width=".18"/>
<path d="M229.7 43.2h9.6l1.1 1.3-1.1 1.2h-9.6l-1.1-1.2z" fill="none" stroke="#ffa049" stroke-width=".18"/>
<g fill="#840000">
<path d="M222.7 28.7h.5l-.1 .1 .3 .8 .3-.8-.1-.1h.4l-.6 1.2z"/>
<path d="M224 29.4h.6l.1 .2-.2 .1 .2 .1a.23 .23 0 0 1-.1 .3 .23 .23 0 0 1-.2 0h-.4l.1-.3h.1v.3a.2 .2 0 0 0 .3-.1 .2 .2 0 0 0 0-.2 .2 .2 0 0 0-.3 0h-.1v-.4h.1v.3a.19 .19 0 0 0 .3 0 .19 .19 0 0 0 0-.3 .19 .19 0 0 0-.3 0z"/>
<path d="M224.8 29.4h.3l-.1 .5 .2 .2 .2-.2-.1-.5h.3l-.1 .4a.3 .3 0 0 1-.3 .3 .3 .3 0 0 1-.3-.3z"/>
<path d="M225.7 29.4l.4-.1v.3l-.2-.2-.1 .1v.1a.28 .28 0 0 1 .4 .3 .28 .28 0 0 1-.5 .2v-.2a.18 .18 0 0 0 .2 .2 .18 .18 0 0 0 .1-.3l-.3-.2z"/>
</g>
<path d="M222.2 27.9h5.6l1.1 1.3-1.1 1.3h-5.6zM244.8 147.3h5.5l1.2 1.3-1.2 1.3h-5.5z" fill="none" stroke="#840000" stroke-width=".18"/>
<path d="M333.9 43.2h12.3l1.1 1.3-1.1 1.2h-12.3l-1.2-1.2zM333.9 45.7h12.3l1.1 1.3-1.1 1.3h-12.3l-1.2-1.3zM240.8 153.7h9.5l1.2 1.2-1.2 1.3h-9.5l-1.1-1.3zM240.8 156.2h9.5l1.2 1.3-1.2 1.3h-9.5l-1.1-1.3zM56.4 242.6h12.3l1.1 1.2-1.1 1.3h-12.3l-1.1-1.3zM56.4 240h12.3l1.1 1.3-1.1 1.3h-12.3l-1.1-1.3z" fill="none" stroke="#ffa049" stroke-width=".18"/>
<g fill="#840000">
<path d="M284.2 46.5h.5a.6 .6 0 0 1 .7 .6 .6 .6 0 0 1-.7 .6h-.5l.2-.1v-1h.1v1a.55 .55 0 0 0 .7-.6 .55 .55 0 0 0-.8-.4z"/>
<path d="M285.6 47.3h.3v.2l-.3 .4 .4-.1-.1 .2h-.4l.3-.5-.1-.2-.2 .1z"/>
<path d="M286 47.1h.5l.1-.5v.5h.4h-.4l-.1 .5v-.5z"/>
<path d="M284.6 41.4h.5a.6 .6 0 0 1 .7 .6 .6 .6 0 0 1-.7 .6h-.5l.2-.1v-1h.1v1a.55 .55 0 0 0 .7-.6 .55 .55 0 0 0-.8-.4z"/>
<path d="M286 42.2h.3v.2l-.3 .4h.4l-.1 .1h-.4l.3-.5-.1-.2-.2 .1z"/>
<path d="M286.5 42.2h.4v.1h-.4z"/>
</g>
<path d="M14 14h57.1v36.8h-57.1zM72.4 14h67.3v36.8h-67.3zM166.4 14h82.5v90.1h-82.5zM250.2 14h156.2v90.1h-156.2zM14 52.1h151.1v109.2h-151.1zM14 198.1h35.5v58.4h-35.5zM50.8 198.1h118.1v85.1h-118.1z" fill="none" stroke="#c2c2c2" stroke-width="1"/>
<g fill="none" stroke="#0000c2" stroke-width=".18">
<path d="M227.3 48.3v19M297.2 53.3h2.5v34.3h-2.5M331.5 48.3v19M135.9 61h1.3v15.2h-1.3M137.2 68.6h1.2M218.4 68.6v-1.3h17.8v1.3M299.7 69.9h2.6M322.6 68.6v-1.3h17.8v1.3M349.2 127v1.3h29.3v-1.3M365.8 128.3v12.7M337.8 144.8h1.3v5.1h-1.3M337.8 154.9h1.3v5.1h-1.3"/>
<path d="M339.1 157.5h1.3M339.1 147.3h1.3M321.3 172.7v-1.2h44.5v1.2M345.4 162.6v8.9M218.4 191.8v8.9M194.3 201.9v-1.2h44.5v1.2"/>
</g>
<g fill="none" stroke="#000" stroke-width=".18">
<path d="M24.1 29.2h6.4M29.2 29.2v2.6h1.3M38.1 39.4v3.8M45.7 29.2h14M59.7 27.9v6.4M59.7 39.4v3.8M82.5 29.2v2.6h1.3M91.4 39.4v3.8M99.1 29.2h27.9M99.1 31.8h7.6v2.5M106.7 39.4v3.8M116.8 29.2v5.1"/>
<path d="M116.8 39.4v3.8M127 27.9v6.4M127 39.4v3.8M195.6 29.2h26.6M195.6 36.8h11.4v41.9M195.6 34.3h13.9v44.4M221 27.9v11.5M279.4 34.3h34.3v44.4M279.4 36.8h31.7v41.9M279.4 29.2h72.4M326.4 38.1h-1.3v1.3M350.5 29.2v2.6h2.6v1.2"/>
<path d="M356.9 29.2h6.3M358.1 29.2v2.6h-2.5v1.2M368.3 36.8v21.6M368.3 39.4h2.5M373.4 29.2h15.2M378.5 29.2v10.2h-2.6M386.1 29.2v21.6h-1.3M22.9 41.9v1.3M34.3 59.7v7.6h-5.1M40.6 59.7v12.7h-11.4M69.8 59.7v25.4M109.2 59.7v2.5"/>
<path d="M125.7 59.7v2.5M195.6 41.9h1.2v2.6h-1.2M195.6 47h1.2v2.5h-1.2M196.8 43.2h17.8v1.3h1.3M215.9 47h-1.3v1.3h-17.8M221 52.1v1.2M279.4 41.9h1.3v2.6h-1.3M279.4 54.6h6.3M279.4 47h1.3v2.5h-1.3M279.4 57.2h6.3M280.7 43.2h35.5v1.3h3.8M281.9 54.6v15.3h-2.5"/>
<path d="M284.5 57.2v15.2h-5.1M320 47h-3.8v1.3h-35.5M325.1 52.1v1.2M368.3 50.8h2.5M378.5 50.8h1.2M29.2 69.9h40.6M30.5 69.9v7.6M63.5 69.9v5M69.8 61h31.8v11.4M87.6 61v1.2M87.6 67.3v1.3M109.2 61h-2.5v11.4"/>
<path d="M109.2 67.3v1.3M125.7 68.6h-5.1v8.9h-6.3M125.7 67.3v2.6M125.7 74.9v1.3M370.8 68.6v1.3M43.2 85.1h3.8v-2.5h26.7v5h20.3M43.2 92.7h7.6M43.2 90.2h7.6M55.9 92.7h8.9M55.9 90.2h8.9M63.5 82.6v16.5M69.8 97.8v11.4"/>
<path d="M74.9 92.7h11.5v48.3h13.9M74.9 90.2h14v48.2h11.4M85.1 82.6h8.9M86.4 97.8h7.6M88.9 92.7h5.1M91.4 82.6v44.4h8.9M114.3 82.6h2.5v44.4h-8.9M114.3 87.6h12.7M172.7 95.3v1.2M180.3 95.3v1.2M207 83.8v10.2h2.5v-10.2M208.3 94v2.5"/>
<path d="M256.5 95.3v1.2M264.2 95.3v1.2M279.4 85.1h1.3v2.5h-1.3M280.7 86.4h5M311.1 83.8v6.4h2.6v-6.4M312.4 90.2v6.3M30.5 108v1.2M63.5 106.7v2.5M104.1 108v2.5M247.6 129.5h3.9v14h2.5M247.6 120.7v1.2M247.6 127v5.1"/>
<path d="M247.6 137.2v1.2M283.2 123.2v-1.3h7.6v1.3M283.2 128.3v1.2M285.7 121.9v15.3M287 120.7v1.2M288.3 121.9v15.3M290.8 128.3v1.2M392.4 129.5v-1.2h-3.8v13.9h-1.3M392.4 134.6v1.3M219.7 158.8v-2.6h11.4v2.6M226.1 154.9v1.3M363.2 157.5v6.3"/>
<path d="M367 149.9h-3.8v2.5M367 144.8h-15.2v6.3h-31.8M387.3 147.3h1.3M184.1 170.2h-2.5v3.8M189.2 170.2h64.8M190.5 170.2v5.1M205.7 179.1h-1.2v10.1h1.2M210.8 179.1h31.8v3.8h11.4M218.4 179.1v2.5M219.7 163.8v2.6M231.1 163.8v8.9h22.9M234.9 179.1v1.2"/>
<path d="M252.7 175.3h1.3M252.7 177.8h1.3M254 163.8h-16.5v2.6h-21.6M254 166.4h-1.3v26.6M320 177.8h21.6v7.6M377.2 162.6v1.2M181.6 181.6v3.8M190.5 180.3v5.1M204.5 184.2h-3.8v1.2M218.4 186.7v2.5M228.6 184.2v6.3M234.9 188v1.2"/>
<path d="M240 184.2h1.3v6.3M254 185.4h-11.4v3.8h-31.8M287 190.5v2.5M320 182.9h1.3v2.5M320 180.3h11.5v5.1M321.3 190.5v2.5M331.5 190.5v2.5M341.6 190.5v2.5M20.3 212.1v6.3M67.3 218.4v1.3M69.8 210.8v22.9h1.3M69.8 212.1h-2.5v1.3"/>
<path d="M83.8 212.1h2.6v14M83.8 210.8v2.6M83.8 218.4v1.3M94 212.1h-2.6v14M94 210.8v2.6M94 218.4v1.3M20.3 223.5v11.4M20.3 227.3h16.5M35.6 227.3v5.1M106.7 236.2h20.3M106.7 233.7h20.3M120.6 233.7v26.6"/>
<path d="M125.7 236.2v24.1M20.3 240v5.1M35.6 242.6v2.5M64.8 252.7v1.3M64.8 259.1v5.1M71.1 248.9h-1.3v12.7h-5M130.8 251.5v-1.3h-7.6v10.1M64.8 269.2v1.3M86.4 261.6v1.3h5v-1.3M88.9 261.6v2.6"/>
</g>
<path d="M279.4 64.8h6.3M279.4 77.5h6.3M279.4 62.2h3.8v15.3M280.7 64.8v15.2h-1.3M114.3 97.8h12.7M114.3 92.7h12.7M119.4 92.7v45.7h-11.5M121.9 97.8v43.2h-14" fill="none" stroke="#008484" stroke-width=".18"/>
<path d="M226.1 47h2.5M226.1 44.5h2.5M330.2 47h2.5M330.2 44.5h2.5M251.5 157.5h2.5M251.5 154.9h2.5M320 148.6h1.3M320 146.1h1.3M320 158.8h1.3M320 156.2h1.3M69.8 243.8h1.3M69.8 241.3h1.3" fill="none" stroke="#ffa049" stroke-width=".18"/>
<g fill="none" stroke="#000084" stroke-width=".18">
<path d="M195 56.5l1.2 1.3M195 54l1.2 1.2M196.2 56.5l-1.2 1.3M196.2 54l-1.2 1.2M372.8 57.8l1.2 1.2M374 57.8l-1.2 1.2M195 61.6l1.2 1.2M195 64.2l1.2 1.2M195 71.8l1.2 1.2M195 76.9l1.2 1.2M195 79.4l1.2 1.2M195 69.2l1.2 1.3"/>
<path d="M196.2 61.6l-1.2 1.2M196.2 64.2l-1.2 1.2M196.2 71.8l-1.2 1.2M196.2 76.9l-1.2 1.2M196.2 79.4l-1.2 1.2M196.2 69.2l-1.2 1.3M42.6 97.2l1.2 1.2M42.6 94.6l1.2 1.3M43.8 97.2l-1.2 1.2M43.8 94.6l-1.2 1.3M195 87l1.2 1.2M195 84.5l1.2 1.2"/>
<path d="M196.2 87l-1.2 1.2M196.2 84.5l-1.2 1.2M27.3 107.3l1.2 1.3M28.5 107.3l-1.2 1.3M366.4 151.8l1.2 1.2M367.6 151.8l-1.2 1.2M386.7 151.8l1.3 1.2M388 151.8l-1.3 1.2M319.4 160.7l1.2 1.2M320.6 160.7l-1.2 1.2M106.1 238.2l1.2 1.2M107.3 238.2l-1.2 1.2"/>
<path d="M106.1 253.4l1.2 1.2M106.1 245.8l1.2 1.2M106.1 250.9l1.2 1.2M106.1 248.3l1.2 1.2M106.1 240.7l1.2 1.2M107.3 253.4l-1.2 1.2M107.3 245.8l-1.2 1.2M107.3 250.9l-1.2 1.2M107.3 248.3l-1.2 1.2M107.3 240.7l-1.2 1.2"/>
</g>
<path d="M227.3 210.8h102.9v30.5h-102.9z" fill="none" stroke="#c8c8c8" stroke-width="1"/>
<g fill="#000">
<path d="M229.6 212.8h.2v.8h1.1v-.8h.2v2h-.2v-.9h-1.1v.9h-.2zM231.7 216.2h.3l.8 2h-.3l-.2-.6h-.8l-.3 .6h-.2l.3-.8h.9l-.3-1-.4 1h-.2zM233.1 212.8h.2v.7a.66 .66 0 0 1 .9 0 .66 .66 0 0 1 .1 .9 .56 .56 0 0 1-.4 .4 .56 .56 0 0 1-.6-.2v.2h-.2v-.7h.2a.44 .44 0 0 0 .5 .5 .44 .44 0 0 0 .3-.7 .4 .4 0 0 0-.5-.4 .4 .4 0 0 0-.3 .6h-.2zM234.7 219.5h.7a1.01 1.01 0 0 1 .9 1 1.01 1.01 0 0 1-.9 1h-.7v-.2h.7a.77 .77 0 0 0 .7-.8 .77 .77 0 0 0-.7-.7h-.5v1.5h-.2zM239 216.4l.3-.2v.5h.2v.2h-.2v.9v.1l.2 .1 .1 .2a.36 .36 0 0 1-.4-.1 .36 .36 0 0 1-.2-.3v-.9h-.1v-.2h.1zM240.1 212.9l.5-.1v.2a.25 .25 0 0 0-.3 .1 .25 .25 0 0 0-.1 .3h.3v.2h-.3v1.2h-.2v-1.2h-.2v-.2h.2zM240.7 212.8h.3v.3h-.3zM247 213l.2-.1v.5h.3v.2h-.3v.8l.1 .2h.2v.2a.36 .36 0 0 1-.4 0 .36 .36 0 0 1-.1-.4v-.8h-.2v-.2h.2zM247.7 212.8h.3v.3h-.3zM254.3 219.5h.9a.56 .56 0 0 1 .7 .5 .56 .56 0 0 1-.6 .6l.7 .9h-.3l-.5-.7-.4-.2h-.3v.9h-.2v-1.1h.8a.35 .35 0 0 0 .5-.3 .35 .35 0 0 0-.4-.3h-.7v.6h-.2zM260.7 219.6a.71 .71 0 0 1 .8 .1 .71 .71 0 0 1 .2 .8 .7 .7 0 0 1-.2 .9 .7 .7 0 0 1-.9 0l-.2-.9h.2a.56 .56 0 0 0 .5 .9 1.18 1.18 0 0 0 0-1.7 .43 .43 0 0 0-.5 .6v.2h-.2l.1-.5zM261.7 216.2h.2v.7a.66 .66 0 0 1 .9 0 .66 .66 0 0 1 .1 .9 .56 .56 0 0 1-.4 .4 .56 .56 0 0 1-.6-.2v.2h-.2v-.8h.2a.44 .44 0 0 0 .5 .6 .44 .44 0 0 0 .3-.7 .4 .4 0 0 0-.5-.4 .4 .4 0 0 0-.3 .5h-.2z"/>
<path d="M266.7 216.1h.2a2.31 2.31 0 0 0 0 2.7h-.2a2.02 2.02 0 0 1 0-2.7zM267.2 216.2h.9a.56 .56 0 0 1 .7 .4 .56 .56 0 0 1-.6 .7l.7 .9h-.3l-.5-.8-.4-.1h-.3v.9h-.2v-1.1h.8a.35 .35 0 0 0 .5-.3 .35 .35 0 0 0-.4-.4h-.7v.7h-.2zM269.2 216.2h1.4v.2h-1.1v.6h1.1v.3h-1.1v.6h1.2v.3h-1.5zM271.1 216.2h.3l.6 1.7 .6-1.7h.4v2h-.3v-1.7l-.6 1.7h-.2l-.6-1.7v1.7h-.2zM273.6 216.3a.71 .71 0 0 1 .8 .1 .71 .71 0 0 1 .2 .8 .7 .7 0 0 1-.2 .8 .7 .7 0 0 1-.9 0l-.2-.8h.2a.56 .56 0 0 0 .5 .8 1.18 1.18 0 0 0 0-1.6 .43 .43 0 0 0-.4 .5l-.1 .3h-.2l.1-.6zM275.6 219.5h.9a.56 .56 0 0 1 .7 .5 .56 .56 0 0 1-.5 .6l.7 .9h-.3l-.6-.7-.3-.2h-.3v.9h-.3v-1.1h.9a.35 .35 0 0 0 .5-.3 .35 .35 0 0 0-.5-.3h-.6v.6h-.3zM286.3 216.9a.54 .54 0 0 1 .8 0v-.7h.3v2h-.3v-.2a.6 .6 0 0 1-.7 .1 .6 .6 0 0 1-.3-.6h.3a.43 .43 0 0 0 .4 .5 .43 .43 0 0 0 .3-.7 .4 .4 0 0 0-.4-.4 .4 .4 0 0 0-.3 .6h-.3zM288.6 216.2h.8a.56 .56 0 0 1 .8 .4 .56 .56 0 0 1-.6 .7l.7 .9h-.3l-.5-.8-.4-.1h-.3v.9h-.2v-1.1h.8a.35 .35 0 0 0 .5-.3 .35 .35 0 0 0-.4-.4h-.7v.7h-.2zM290.6 216.2h1.4v.2h-1.2v.6h1.2v.3h-1.2v.6h1.3v.3h-1.5zM292.4 216.2h.4l.6 1.7 .6-1.7h.3v2h-.2v-1.7l-.6 1.7h-.2l-.6-1.7v1.7h-.3zM294.9 216.7l.7-.5v2h-.2v-1.6l-.5 .3zM299.5 216.2h.2v.7a.52 .52 0 0 1 .6-.2 .52 .52 0 0 1 .4 .6v.9h-.3v-.9a.36 .36 0 0 0-.4-.4 .36 .36 0 0 0-.3 .5v.8h-.2z"/>
<path d="M301 216.2h.3v.2h-.3zM303.2 216.2h.3v.7a.52 .52 0 0 1 .6-.2 .52 .52 0 0 1 .3 .6v.9h-.2v-.9a.36 .36 0 0 0-.5-.4 .36 .36 0 0 0-.2 .5v.8h-.3zM304.8 216.1h.1a2.02 2.02 0 0 1 0 2.7h-.1a2.31 2.31 0 0 0 0-2.7zM229.4 220.7h.8v.2h-.8zM229.4 224h.8v.3h-.8zM229.4 230.8h.8v.2h-.8zM229.4 237.5h.8v.2h-.8zM231.4 223l.3-.1a.73 .73 0 0 1 1 .6h-.3a.44 .44 0 0 0-.4-.4 .44 .44 0 0 0-.4 .5 1.18 1.18 0 0 1 1.2 .6 .8 .8 0 0 1-.8 .7 .8 .8 0 0 1-.8-.6l.2-.1a.55 .55 0 0 0 .5 .5 .55 .55 0 0 0 .6-.4l-.2-.2a1.02 1.02 0 0 1-1.1-.6zM231.4 226.4l.3-.1a.73 .73 0 0 1 1 .5h-.3a.44 .44 0 0 0-.4-.4 .44 .44 0 0 0-.4 .5v.1a1.18 1.18 0 0 1 1.2 .6 .8 .8 0 0 1-.8 .7 .8 .8 0 0 1-.8-.7h.2a.55 .55 0 0 0 .5 .5 .55 .55 0 0 0 .6-.5l-.2-.2a1.02 1.02 0 0 1-1.1-.5zM231.2 219.5h.3v1.8h1v.2h-1.3zM231.3 236.3h1.4v.3h-1.2v.6h1.1v.2h-1.1v.7h1.3v.2h-1.5zM232 230.2h.2v.2a.52 .52 0 0 1 .6-.2 .52 .52 0 0 1 .4 .5v.9h-.3v-.9a.36 .36 0 0 0-.4-.4 .36 .36 0 0 0-.3 .5v.8h-.2z"/>
<path d="M232.8 219.5h1.5v.3h-1.2v.6h1.1v.2h-1.1v.7h1.2v.2h-1.5zM233.1 236.9h.2v.2a.52 .52 0 0 1 .6-.2 .52 .52 0 0 1 .4 .5v.9h-.3v-.8a.36 .36 0 0 0-.4-.4 .36 .36 0 0 0-.3 .4v.8h-.2zM233.1 223.1l.3-.2v.5h.2v.2h-.2v.9v.2h.2l.1 .2a.36 .36 0 0 1-.4 0 .36 .36 0 0 1-.2-.4v-.9h-.1v-.2h.1zM233.9 223.4h.2v.3l.2-.3h.3v.3a.33 .33 0 0 0-.4 .1 .33 .33 0 0 0-.1 .3v.8h-.2zM233.7 230.3a.54 .54 0 0 1 .8 0v-.7h.2v2h-.2v-.2a.6 .6 0 0 1-.7 .2 .6 .6 0 0 1-.3-.7h.2a.43 .43 0 0 0 .5 .5 .43 .43 0 0 0 .3-.6 .4 .4 0 0 0-.5-.5 .4 .4 0 0 0-.3 .6h-.2zM233.7 233.7a.54 .54 0 0 1 .8 0v-.7h.2v2h-.2v-.2a.6 .6 0 0 1-.7 .1 .6 .6 0 0 1-.3-.6h.2a.43 .43 0 0 0 .5 .5 .43 .43 0 0 0 .3-.7 .4 .4 0 0 0-.5-.4 .4 .4 0 0 0-.3 .6h-.2zM235.1 230.2h.3v1.4h-.3zM235.1 233h.3v.2h-.3zM235.4 226.3l.6-.1-.1 .3a.25 .25 0 0 0-.3 0 .25 .25 0 0 0 0 .3h.3v.2h-.3v1.3h-.3v-1.3h-.2v-.2h.2zM234.8 237a.65 .65 0 0 1 .8-.1 .65 .65 0 0 1 .2 .8l.1 .6h-.3v-.1a.57 .57 0 0 1-.6 .2 .57 .57 0 0 1-.4-.5h.2l.3 .3a.44 .44 0 0 0 .5-.6l-1 .3a.65 .65 0 0 1 .8-.4 .22 .22 0 0 0 .1-.3 .22 .22 0 0 0-.3-.1h-.2l-.2 .2h-.2zM234.9 223.6a.65 .65 0 0 1 .9-.1 .65 .65 0 0 1 .2 .8l.1 .6h-.3l-.1-.2a.57 .57 0 0 1-.5 .3 .57 .57 0 0 1-.5-.5h.3l.3 .2a.44 .44 0 0 0 .4-.5l-1 .3a.65 .65 0 0 1 .9-.5 .22 .22 0 0 0 .1-.3 .22 .22 0 0 0-.3-.1l-.3 .1-.1 .2h-.2zM235.6 230.2h.2l.4 1.1 .5-1.1h.2l-.5 1.4h-.3z"/>
<path d="M236.2 236.3h.2v.8a.66 .66 0 0 1 .9 0 .66 .66 0 0 1 .1 .8 .56 .56 0 0 1-.4 .5 .56 .56 0 0 1-.6-.2v.1h-.2v-.7h.2a.44 .44 0 0 0 .5 .6 .44 .44 0 0 0 .3-.7 .4 .4 0 0 0-.5-.4 .4 .4 0 0 0-.3 .5h-.2zM236.4 223.4h.2v.2a.64 .64 0 0 1 .8 0 .64 .64 0 0 1 .2 .8 .57 .57 0 0 1-.4 .5 .57 .57 0 0 1-.6-.2v.8h-.2v-1.3h.2a.44 .44 0 0 0 .5 .5 .44 .44 0 0 0 .3-.7 .41 .41 0 0 0-.5-.4 .41 .41 0 0 0-.3 .6h-.2zM237.1 230.2h.3v1.4h-.3zM237.1 233h.3v.2h-.3zM237.4 220.1h.3v1.4h-.3zM238.1 220.2l.2-.1a.57 .57 0 0 1 .8 .4h-.2a.29 .29 0 0 0-.3-.3 .29 .29 0 0 0-.3 .4 .81 .81 0 0 1 .9 .5 .62 .62 0 0 1-.6 .5 .62 .62 0 0 1-.6-.5h.2a.32 .32 0 0 0 .4 .3 .32 .32 0 0 0 .2-.4 .71 .71 0 0 1-.8-.6zM237.9 230.3a.54 .54 0 0 1 .8 0v-.7h.2v2h-.2v-.2a.6 .6 0 0 1-.7 .2 .6 .6 0 0 1-.3-.7h.2a.44 .44 0 0 0 .5 .5 .44 .44 0 0 0 .3-.6 .4 .4 0 0 0-.5-.5 .4 .4 0 0 0-.3 .6h-.2zM237.9 233.7a.54 .54 0 0 1 .8 0v-.7h.2v2h-.2v-.2a.6 .6 0 0 1-.7 .1 .6 .6 0 0 1-.3-.6h.2a.44 .44 0 0 0 .5 .5 .44 .44 0 0 0 .3-.7 .4 .4 0 0 0-.5-.4 .4 .4 0 0 0-.3 .6h-.2zM238.5 237.1a.68 .68 0 0 1 .8-.2 .68 .68 0 0 1 .3 .8h-1.1a.42 .42 0 0 0 .4 .5 .42 .42 0 0 0 .5-.3h.2a.69 .69 0 0 1-.8 .4 .69 .69 0 0 1-.5-.8h1.1a.41 .41 0 0 0-.4-.4 .41 .41 0 0 0-.4 .4h-.3zM238.8 223.6a.71 .71 0 0 1 1 .1 .71 .71 0 0 1-.1 1 .71 .71 0 0 1-1.1-.2v-.3h.2a.46 .46 0 0 0 .6 .5 .46 .46 0 0 0 .3-.7 .43 .43 0 0 0-.5-.4 .43 .43 0 0 0-.4 .6h-.2zM239.3 230.2h.2v.8a.37 .37 0 0 0 .4 .5 .37 .37 0 0 0 .3-.6v-.7h.3v1.4h-.2v-.2a.52 .52 0 0 1-.7 .2 .52 .52 0 0 1-.3-.5zM240.7 236.3h.3v.8a.66 .66 0 0 1 .8 0 .66 .66 0 0 1 .1 .8 .56 .56 0 0 1-.4 .5 .56 .56 0 0 1-.6-.2v.1h-.2v-.7h.2a.44 .44 0 0 0 .5 .6 .44 .44 0 0 0 .3-.7 .4 .4 0 0 0-.5-.4 .4 .4 0 0 0-.3 .5h-.2z"/>
<path d="M240.2 223.4h.3v.2a.64 .64 0 0 1 .8 0 .64 .64 0 0 1 .2 .8 .57 .57 0 0 1-.4 .5 .57 .57 0 0 1-.6-.2v.8h-.3v-1.3h.3a.44 .44 0 0 0 .5 .5 .44 .44 0 0 0 .2-.7 .41 .41 0 0 0-.4-.4 .41 .41 0 0 0-.3 .6h-.3zM240.4 220.2a.65 .65 0 0 1 .8-.1 .65 .65 0 0 1 .2 .8l.1 .6h-.3v-.1a.57 .57 0 0 1-.6 .2 .57 .57 0 0 1-.4-.5h.2l.3 .3a.44 .44 0 0 0 .5-.6l-1 .3a.65 .65 0 0 1 .8-.4 .22 .22 0 0 0 .1-.3 .22 .22 0 0 0-.3-.1h-.2l-.2 .2h-.2zM241 230.3a.65 .65 0 0 1 .8-.1 .65 .65 0 0 1 .2 .8l.1 .6h-.2l-.1-.2a.57 .57 0 0 1-.6 .3 .57 .57 0 0 1-.4-.5h.2l.3 .3a.44 .44 0 0 0 .5-.6l-1 .3a.65 .65 0 0 1 .8-.5 .22 .22 0 0 0 .1-.3 .22 .22 0 0 0-.3-.1l-.2 .1-.1 .2h-.3zM241.8 223.1l.3-.2v.5h.2v.2h-.2v.9v.2h.2l.1 .2a.36 .36 0 0 1-.4 0 .36 .36 0 0 1-.2-.4v-.9h-.1v-.2h.1zM242.6 222.9h.2v.3h-.2zM242.6 223.4h.2v1.5h-.2zM241.9 220.2a.61 .61 0 0 1 1.1 .3h-.3a.43 .43 0 0 0-.6-.2 .43 .43 0 0 0-.1 .7 .38 .38 0 0 0 .3 .4 .38 .38 0 0 0 .4-.4h.3a.68 .68 0 0 1-.9 .5 .68 .68 0 0 1-.3-1zM242.4 237a.65 .65 0 0 1 .8-.1 .65 .65 0 0 1 .2 .8l.1 .6h-.2l-.1-.1a.57 .57 0 0 1-.6 .2 .57 .57 0 0 1-.4-.5h.2l.3 .3a.44 .44 0 0 0 .5-.6l-1 .3a.65 .65 0 0 1 .8-.4 .22 .22 0 0 0 .1-.3 .22 .22 0 0 0-.3-.1h-.2l-.1 .2h-.3zM243.2 219.7l.3-.1v.5h.2v.2h-.2v.8v.2h.2l.1 .2a.36 .36 0 0 1-.4 0 .36 .36 0 0 1-.2-.4v-.8h-.1v-.2h.1zM243.3 223.6a.71 .71 0 0 1 1 .1 .71 .71 0 0 1-.1 1 .71 .71 0 0 1-1-.2l-.1-.3h.3a.46 .46 0 0 0 .5 .5 .46 .46 0 0 0 .3-.7 .43 .43 0 0 0-.5-.4 .43 .43 0 0 0-.3 .6h-.3zM244 220.1h.2v1.4h-.2zM243.9 236.5l.2-.1v.5h.3v.2h-.3v.8l.1 .2h.2v.2a.36 .36 0 0 1-.4 0 .36 .36 0 0 1-.1-.4v-.8h-.2v-.2h.2z"/>
<path d="M243.8 230.2h.2v.2a.64 .64 0 0 1 .9-.1 .64 .64 0 0 1 .1 .9 .57 .57 0 0 1-.4 .4 .57 .57 0 0 1-.5-.1v.7h-.3v-1.3h.2a.44 .44 0 0 0 .6 .5 .44 .44 0 0 0 .2-.7 .41 .41 0 0 0-.5-.4 .41 .41 0 0 0-.3 .6h-.2zM244.8 223.4h.2v.3a.52 .52 0 0 1 .6-.3 .52 .52 0 0 1 .3 .6v.9h-.2v-.9a.36 .36 0 0 0-.4-.4 .36 .36 0 0 0-.3 .5v.8h-.2zM244.4 220.1h.3l.4 1.1 .4-1.1h.3l-.6 1.4h-.2zM244.6 236.5l.3-.1v.5h.2v.2h-.2v.8v.2h.2l.1 .2a.36 .36 0 0 1-.4 0 .36 .36 0 0 1-.2-.4v-.8h-.1v-.2h.1zM245.5 230.3a.71 .71 0 0 1 1 .1 .71 .71 0 0 1-.2 1.1 .71 .71 0 0 1-1-.3v-.3h.2a.46 .46 0 0 0 .6 .5 .46 .46 0 0 0 .3-.7 .43 .43 0 0 0-.5-.4 .43 .43 0 0 0-.4 .6h-.2zM245.5 237.1a.68 .68 0 0 1 .8-.2 .68 .68 0 0 1 .3 .8h-1.1a.42 .42 0 0 0 .4 .5 .42 .42 0 0 0 .5-.3h.2a.69 .69 0 0 1-.8 .4 .69 .69 0 0 1-.5-.8h1.1a.41 .41 0 0 0-.4-.4 .41 .41 0 0 0-.4 .4h-.3zM246.3 223.6l.3-.2a.57 .57 0 0 1 .8 .4l-.3 .1a.29 .29 0 0 0-.3-.3 .29 .29 0 0 0-.2 .3 .81 .81 0 0 1 .8 .6 .62 .62 0 0 1-.6 .4 .62 .62 0 0 1-.6-.4l.3-.1a.32 .32 0 0 0 .3 .4 .32 .32 0 0 0 .3-.4 .71 .71 0 0 1-.8-.7zM246.1 220.3a.68 .68 0 0 1 .8-.2 .68 .68 0 0 1 .3 .8h-1a.42 .42 0 0 0 .3 .5 .42 .42 0 0 0 .5-.3h.2a.69 .69 0 0 1-.8 .4 .69 .69 0 0 1-.5-.8h1.1a.41 .41 0 0 0-.4-.4 .41 .41 0 0 0-.4 .4h-.3zM246.9 236.9h.3v.2l.2-.2h.2v.3a.33 .33 0 0 0-.4 0 .33 .33 0 0 0 0 .4v.7h-.3zM246.8 230.2h.2l.3 1.1 .3-1.1h.3l.3 1.1 .3-1.1h.2l-.4 1.4h-.3l-.3-1.1-.2 1.1h-.3zM246.3 226.9a.54 .54 0 0 1 .8 .1v-.7h.2v2h-.2v-.2a.6 .6 0 0 1-.7 .1 .6 .6 0 0 1-.3-.7h.2a.44 .44 0 0 0 .5 .6 .44 .44 0 0 0 .3-.7 .4 .4 0 0 0-.5-.4 .4 .4 0 0 0-.3 .5h-.2zM247.7 236.9h.3l.4 1.2 .4-1.2h.3l-.6 1.5a.51 .51 0 0 1-.6 .5l-.1-.2a.32 .32 0 0 0 .5-.4z"/>
<path d="M248.6 223.6a.68 .68 0 0 1 .8-.1 .68 .68 0 0 1 .3 .7h-1a.42 .42 0 0 0 .3 .5 .42 .42 0 0 0 .5-.3l.2 .1a.69 .69 0 0 1-.8 .4 .69 .69 0 0 1-.5-.9h1.1a.41 .41 0 0 0-.4-.4 .41 .41 0 0 0-.4 .4h-.3zM249.1 220.2a.71 .71 0 0 1 1 .2 .71 .71 0 0 1-.2 1 .71 .71 0 0 1-1-.3v-.3h.2a.46 .46 0 0 0 .5 .6 .46 .46 0 0 0 .4-.7 .43 .43 0 0 0-.5-.4 .43 .43 0 0 0-.4 .5h-.2zM249.1 230.3a.68 .68 0 0 1 .8-.1 .68 .68 0 0 1 .3 .8h-1.1a.42 .42 0 0 0 .3 .4 .42 .42 0 0 0 .5-.2h.3a.69 .69 0 0 1-.9 .4 .69 .69 0 0 1-.4-.8h1a.41 .41 0 0 0-.4-.5 .41 .41 0 0 0-.4 .5h-.2zM250 223.4h.3v.3a.52 .52 0 0 1 .6-.3 .52 .52 0 0 1 .3 .6v.9h-.2v-.9a.36 .36 0 0 0-.4-.4 .36 .36 0 0 0-.3 .5v.8h-.3zM250.5 230.2h.2v.2l.3-.3 .2 .1v.2a.33 .33 0 0 0-.4 .1 .33 .33 0 0 0-.1 .4v.7h-.2zM250.3 220.1h.3l.3 1.1 .3-1.1h.3l.2 1.1 .4-1.1h.2l-.4 1.4h-.3l-.3-1.1-.3 1.1h-.2zM250.2 237a.71 .71 0 0 1 1 .2 .71 .71 0 0 1-.2 1 .71 .71 0 0 1-1-.3l-.1-.3h.3a.46 .46 0 0 0 .5 .6 .46 .46 0 0 0 .3-.7 .43 .43 0 0 0-.5-.4 .43 .43 0 0 0-.3 .5h-.3zM252.3 230.3l.2-.1a.57 .57 0 0 1 .8 .3l-.3 .1a.29 .29 0 0 0-.3-.3 .29 .29 0 0 0-.2 .3 .81 .81 0 0 1 .8 .6 .62 .62 0 0 1-.6 .5 .62 .62 0 0 1-.6-.5h.3a.32 .32 0 0 0 .3 .3 .32 .32 0 0 0 .3-.4 .71 .71 0 0 1-.8-.6zM251.6 236.9h.2v.2a.64 .64 0 0 1 .9-.1 .64 .64 0 0 1 .1 .9 .57 .57 0 0 1-.4 .4 .57 .57 0 0 1-.6-.1v.7h-.2v-1.3h.2a.44 .44 0 0 0 .5 .6 .44 .44 0 0 0 .3-.7 .41 .41 0 0 0-.5-.4 .41 .41 0 0 0-.3 .5h-.2zM251.7 223.6a.65 .65 0 0 1 .8-.1 .65 .65 0 0 1 .3 .8v.6h-.2l-.1-.2a.57 .57 0 0 1-.5 .3 .57 .57 0 0 1-.5-.5h.3l.3 .2a.44 .44 0 0 0 .4-.5l-1 .3a.65 .65 0 0 1 .9-.5 .22 .22 0 0 0 .1-.3 .22 .22 0 0 0-.3-.1l-.3 .1-.1 .2h-.2zM253.1 222.9h.3v.7a.66 .66 0 0 1 .9 0 .66 .66 0 0 1 .1 .9 .56 .56 0 0 1-.5 .4 .56 .56 0 0 1-.5-.2v.2h-.3v-.7h.3a.44 .44 0 0 0 .5 .5 .44 .44 0 0 0 .2-.7 .4 .4 0 0 0-.4-.4 .4 .4 0 0 0-.3 .6h-.3zM253.2 236.5l.2-.1v.5h.3v.2h-.3v.8l.1 .2h.2v.2a.36 .36 0 0 1-.4 0 .36 .36 0 0 1-.1-.4v-.8h-.2v-.2h.2z"/>
<path d="M253.8 219.5h.1a2.31 2.31 0 0 0 0 2.6h-.1a2.02 2.02 0 0 1 0-2.6zM253.4 230.2h.3l.3 1.1 .3-1.1h.3l.3 1.1 .3-1.1h.2l-.4 1.4h-.3l-.3-1.1-.3 1.1h-.2zM253.9 236.9h.3v1.4h-.3zM254.7 237a.71 .71 0 0 1 1 .2 .71 .71 0 0 1-.2 1 .71 .71 0 0 1-1-.3v-.3h.2a.46 .46 0 0 0 .5 .6 .46 .46 0 0 0 .4-.7 .43 .43 0 0 0-.5-.4 .43 .43 0 0 0-.4 .5h-.2zM255.6 230.2h.3v1.4h-.3zM255.4 223.6a.68 .68 0 0 1 .8-.1 .68 .68 0 0 1 .4 .7h-1.1a.42 .42 0 0 0 .3 .5 .42 .42 0 0 0 .5-.3l.3 .1a.69 .69 0 0 1-.9 .4 .69 .69 0 0 1-.4-.9h1a.41 .41 0 0 0-.4-.4 .41 .41 0 0 0-.4 .4h-.2zM256.1 236.9h.2v.2a.52 .52 0 0 1 .7-.2 .52 .52 0 0 1 .3 .5v.9h-.3v-.8a.36 .36 0 0 0-.4-.4 .36 .36 0 0 0-.2 .4v.8h-.3zM255.7 226.4l.2-.1v.5h.3v.2h-.3v.8l.1 .2h.2v.3a.36 .36 0 0 1-.4-.1 .36 .36 0 0 1-.1-.4v-.8h-.2v-.2h.2zM256.3 219.5h1.4v.3h-1.1v.6h1.1v.2h-1.1v.7h1.2v.2h-1.5zM256.4 226.3h.3v.2h-.3zM256.3 229.8l.2-.1v.5h.3v.2h-.3v.8l.1 .2h.2v.2a.36 .36 0 0 1-.4 0 .36 .36 0 0 1-.1-.4v-.8h-.2v-.2h.2zM257.2 230.3a.61 .61 0 0 1 1 .3h-.2a.43 .43 0 0 0-.7-.2 .43 .43 0 0 0-.1 .6 .38 .38 0 0 0 .4 .4 .38 .38 0 0 0 .4-.3h.2a.68 .68 0 0 1-.9 .5 .68 .68 0 0 1-.3-1z"/>
<path d="M257 223.6a.54 .54 0 0 1 .8 0v-.7h.3v2h-.3v-.2a.6 .6 0 0 1-.7 .1 .6 .6 0 0 1-.3-.6h.2a.44 .44 0 0 0 .5 .5 .44 .44 0 0 0 .3-.7 .4 .4 0 0 0-.4-.4 .4 .4 0 0 0-.4 .6h-.2zM258.1 219.5h.4l.6 1.7 .6-1.7h.4v2h-.3v-1.6l-.6 1.6h-.2l-.6-1.7v1.7h-.3zM258.4 229.6h.3v.7a.52 .52 0 0 1 .6-.1 .52 .52 0 0 1 .3 .5v.9h-.2v-.9a.36 .36 0 0 0-.5-.4 .36 .36 0 0 0-.2 .5v.8h-.3zM258.6 236.4l.5-.1v.2a.25 .25 0 0 0-.3 .1 .25 .25 0 0 0-.1 .3h.3v.2h-.3v1.2h-.2v-1.2h-.2v-.2h.2zM258.2 233.2l.2-.2v.5h.3v.2h-.3v.9l.1 .1 .2 .1v.2a.36 .36 0 0 1-.4-.1 .36 .36 0 0 1-.1-.3v-.9h-.2v-.2h.2zM259.7 222.9h.2a2.31 2.31 0 0 0 0 2.6h-.2a2.02 2.02 0 0 1 0-2.6zM259.3 237a.71 .71 0 0 1 1.1 .2 .71 .71 0 0 1-.2 1 .71 .71 0 0 1-1-.3l-.1-.3h.3a.46 .46 0 0 0 .5 .6 .46 .46 0 0 0 .3-.7 .43 .43 0 0 0-.5-.4 .43 .43 0 0 0-.3 .5h-.3zM260 230.2h.2v1.4h-.2zM260.6 230.2h.2v.2a.52 .52 0 0 1 .7-.2 .52 .52 0 0 1 .3 .5v.9h-.3v-.9a.36 .36 0 0 0-.4-.4 .36 .36 0 0 0-.2 .5v.8h-.3zM260.8 236.9h.2v.2l.2-.2h.3v.3a.33 .33 0 0 0-.4 0 .33 .33 0 0 0-.1 .4v.7h-.2zM260.4 223.1a.88 .88 0 0 1 1.4 .3l-.2 .1a.65 .65 0 0 0-.9-.3 .65 .65 0 0 0-.3 .8 .62 .62 0 0 0 .5 .7 .62 .62 0 0 0 .7-.5l.3 .1a.95 .95 0 0 1-1.3 .5 .95 .95 0 0 1-.4-1.3zM262.2 222.9h1.4v.2h-1.1v.7h.9v.2h-.9v.9h-.3z"/>
<path d="M262.3 230.3a.57 .57 0 0 1 .8 0v-.1h.2v1.2a.63 .63 0 0 1-.4 .8 .63 .63 0 0 1-.8-.5l.3 .1a.4 .4 0 0 0 .5 .2 .4 .4 0 0 0 .2-.6 .61 .61 0 0 1-.7 .1 .61 .61 0 0 1-.3-.6h.2a.44 .44 0 0 0 .5 .5 .44 .44 0 0 0 .3-.7 .4 .4 0 0 0-.5-.4 .4 .4 0 0 0-.3 .6h-.2zM262.5 236.9h.2v.2a.64 .64 0 0 1 .9-.1 .64 .64 0 0 1 .1 .9 .57 .57 0 0 1-.4 .4 .57 .57 0 0 1-.6-.1v.7h-.2v-1.3h.2a.44 .44 0 0 0 .5 .6 .44 .44 0 0 0 .3-.7 .41 .41 0 0 0-.5-.4 .41 .41 0 0 0-.3 .5h-.2zM262.8 220.1h1.3v.3h-1.3zM262.8 220.7h1.3v.3h-1.3zM264.2 237a.71 .71 0 0 1 1 .2 .71 .71 0 0 1-.2 1 .71 .71 0 0 1-1-.3l-.1-.3h.3a.46 .46 0 0 0 .5 .6 .46 .46 0 0 0 .3-.7 .43 .43 0 0 0-.5-.4 .43 .43 0 0 0-.3 .5h-.3zM264.1 223.1a.92 .92 0 0 1 1.6 .4h-.3a.72 .72 0 0 0-1-.3 .72 .72 0 0 0-.2 1 .79 .79 0 0 0 1.2 .3v-.4h-.6v-.2h.9v.7a1.08 1.08 0 0 1-1.5 .1 1.08 1.08 0 0 1-.1-1.6zM264.6 230.3a.68 .68 0 0 1 .8-.1 .68 .68 0 0 1 .4 .8h-1.1a.42 .42 0 0 0 .3 .4 .42 .42 0 0 0 .5-.2h.2a.69 .69 0 0 1-.8 .4 .69 .69 0 0 1-.5-.8h1.1a.41 .41 0 0 0-.4-.5 .41 .41 0 0 0-.4 .5h-.3zM265.6 233h.2v.2h-.2zM265.6 236.9h.2v.2l.2-.2h.3v.3a.33 .33 0 0 0-.4 0 .33 .33 0 0 0-.1 .4v.7h-.2zM265.8 225.3h1.7v.2h-1.7zM265.6 226.3h.2v.7a.66 .66 0 0 1 .9 0 .66 .66 0 0 1 .1 .9 .56 .56 0 0 1-.4 .4 .56 .56 0 0 1-.6-.2v.2h-.2v-.8h.2a.44 .44 0 0 0 .5 .6 .44 .44 0 0 0 .3-.7 .4 .4 0 0 0-.5-.4 .4 .4 0 0 0-.3 .5h-.2zM266.1 230.2h.2v.2a.52 .52 0 0 1 .6-.2 .52 .52 0 0 1 .3 .5v.9h-.2v-.9a.36 .36 0 0 0-.4-.4 .36 .36 0 0 0-.3 .5v.8h-.2z"/>
<path d="M265.9 220.2a.71 .71 0 0 1 1.1 .2 .71 .71 0 0 1-.2 1 .71 .71 0 0 1-1-.3l-.1-.3h.3a.46 .46 0 0 0 .5 .6 .46 .46 0 0 0 .3-.7 .43 .43 0 0 0-.5-.4 .43 .43 0 0 0-.3 .5h-.3zM266.6 236.5l.2-.1v.5h.3v.2h-.3v.8l.1 .2h.2v.2a.36 .36 0 0 1-.4 0 .36 .36 0 0 1-.1-.4v-.8h-.2v-.2h.2zM267.8 223l.3-.1a.73 .73 0 0 1 1 .6h-.3a.44 .44 0 0 0-.5-.4 .44 .44 0 0 0-.3 .5 1.18 1.18 0 0 1 1.1 .6 .8 .8 0 0 1-.7 .7 .8 .8 0 0 1-.8-.6l.2-.1a.55 .55 0 0 0 .5 .5 .55 .55 0 0 0 .6-.4l-.2-.2a1.02 1.02 0 0 1-1.1-.6zM267.2 220.1h.2l.4 1.1 .3-1.1h.2l.3 1.1 .3-1.1h.3l-.5 1.4h-.2l-.3-1.1-.3 1.1h-.3zM267.9 236.9h.3l.3 1.1 .3-1.1h.2l.3 1.1 .4-1.1h.2l-.5 1.4h-.2l-.3-1.1-.3 1.1h-.3zM267.7 230.3a.65 .65 0 0 1 .9-.1 .65 .65 0 0 1 .2 .8l.1 .6h-.3v-.2a.57 .57 0 0 1-.6 .3 .57 .57 0 0 1-.5-.5h.3l.3 .3a.44 .44 0 0 0 .4-.6l-1 .3a.65 .65 0 0 1 .9-.5 .22 .22 0 0 0 .1-.3 .22 .22 0 0 0-.3-.1l-.3 .1-.1 .2h-.2zM269.2 229.6h.2v.7a.66 .66 0 0 1 .9 0 .66 .66 0 0 1 .1 .9 .56 .56 0 0 1-.4 .4 .56 .56 0 0 1-.6-.2v.2h-.2v-.7h.2a.44 .44 0 0 0 .5 .5 .44 .44 0 0 0 .3-.7 .4 .4 0 0 0-.5-.4 .4 .4 0 0 0-.3 .6h-.2zM269.5 222.9h1.5v.2h-1.2v.6h1.1v.3h-1.1v.7h1.2v.2h-1.5zM269.4 226.9a.54 .54 0 0 1 .8 .1v-.7h.3v2h-.2v-.2a.6 .6 0 0 1-.8 .1 .6 .6 0 0 1-.3-.7h.3a.44 .44 0 0 0 .5 .6 .44 .44 0 0 0 .3-.7 .4 .4 0 0 0-.5-.4 .4 .4 0 0 0-.3 .5h-.3zM270.3 220.2a.65 .65 0 0 1 .8-.1 .65 .65 0 0 1 .2 .8l.1 .6h-.2l-.1-.1a.57 .57 0 0 1-.6 .2 .57 .57 0 0 1-.4-.5h.2l.3 .3a.44 .44 0 0 0 .5-.6l-1 .3a.65 .65 0 0 1 .8-.4 .22 .22 0 0 0 .2-.3 .22 .22 0 0 0-.4-.1h-.2l-.1 .2h-.3zM271.3 236.3h.2a2.31 2.31 0 0 0 0 2.6h-.2a2.02 2.02 0 0 1 0-2.6zM271.4 222.9h.2v1.8h1v.2h-1.2z"/>
<path d="M271.7 220.1h.2v.2a.52 .52 0 0 1 .7-.2 .52 .52 0 0 1 .3 .5v.9h-.2v-.8a.36 .36 0 0 0-.4-.4 .36 .36 0 0 0-.3 .4v.8h-.3zM271.4 230.3a.68 .68 0 0 1 .9-.1 .68 .68 0 0 1 .3 .8h-1.1a.42 .42 0 0 0 .3 .4 .42 .42 0 0 0 .5-.2h.3a.69 .69 0 0 1-.9 .4 .69 .69 0 0 1-.4-.8h1a.41 .41 0 0 0-.4-.5 .41 .41 0 0 0-.4 .5h-.2zM272.1 226.2h.2a2.31 2.31 0 0 0 0 2.6h-.2a2.02 2.02 0 0 1 0-2.6zM271.8 236.3h.8a.51 .51 0 0 1 .6 .3 .51 .51 0 0 1-.2 .7 .57 .57 0 0 1 .3 .7 .57 .57 0 0 1-.7 .3h-.8v-.2h.8a.37 .37 0 0 0 .5-.4 .37 .37 0 0 0-.5-.3h-.5v.7h-.3v-.9h.7a.32 .32 0 0 0 .5-.2 .32 .32 0 0 0-.3-.4h-.6v.6h-.3zM273.1 223a.71 .71 0 0 1 .9 .1 .71 .71 0 0 1 .1 .8 .7 .7 0 0 1-.2 .9 .7 .7 0 0 1-.9-.1l-.2-.8h.3a.56 .56 0 0 0 .5 .8 1.18 1.18 0 0 0 0-1.6 .43 .43 0 0 0-.5 .5v.3h-.3l.1-.6zM272.8 226.5a.88 .88 0 0 1 1.5 .3l-.3 .1a.65 .65 0 0 0-.9-.4 .65 .65 0 0 0-.3 .9 .62 .62 0 0 0 .6 .7 .62 .62 0 0 0 .6-.5h.3a.95 .95 0 0 1-1.3 .6 .95 .95 0 0 1-.4-1.3zM273 230.3a.54 .54 0 0 1 .8 0v-.7h.3v2h-.3v-.2a.6 .6 0 0 1-.7 .2 .6 .6 0 0 1-.3-.7h.3a.44 .44 0 0 0 .5 .5 .44 .44 0 0 0 .2-.6 .4 .4 0 0 0-.4-.5 .4 .4 0 0 0-.3 .6h-.3zM273.4 220.2a.54 .54 0 0 1 .8 .1v-.8h.3v2h-.3v-.1a.6 .6 0 0 1-.7 .1 .6 .6 0 0 1-.3-.7h.2a.44 .44 0 0 0 .5 .6 .44 .44 0 0 0 .3-.7 .4 .4 0 0 0-.5-.4 .4 .4 0 0 0-.3 .5h-.2zM274.7 226.3h1.3v.2h-1.1v.6h1v.2h-1v1h-.2zM274.8 233h.2v.7a.66 .66 0 0 1 .9 0 .66 .66 0 0 1 .1 .9 .56 .56 0 0 1-.5 .4 .56 .56 0 0 1-.5-.2v.2h-.2v-.8h.2a.44 .44 0 0 0 .5 .6 .44 .44 0 0 0 .3-.7 .4 .4 0 0 0-.5-.4 .4 .4 0 0 0-.3 .5h-.2zM273.9 236.6a.88 .88 0 0 1 1.5 .3h-.3a.65 .65 0 0 0-.9-.3 .65 .65 0 0 0-.3 .9 .62 .62 0 0 0 .6 .6 .62 .62 0 0 0 .6-.5l.3 .1a.95 .95 0 0 1-1.3 .6 .95 .95 0 0 1-.4-1.4zM275.5 238.7h1.6v.2h-1.6z"/>
<path d="M275.7 229.6h.2a2.31 2.31 0 0 0 0 2.6h-.2a2.02 2.02 0 0 1 0-2.6zM275.4 223.6a.65 .65 0 0 1 .8-.1 .65 .65 0 0 1 .2 .8l.1 .6h-.3v-.2a.57 .57 0 0 1-.6 .3 .57 .57 0 0 1-.5-.5h.3l.3 .2a.44 .44 0 0 0 .5-.5l-1.1 .3a.65 .65 0 0 1 .9-.5 .22 .22 0 0 0 .1-.3 .22 .22 0 0 0-.3-.1l-.2 .1-.2 .2h-.2zM276.8 223.4h.2v.3a.52 .52 0 0 1 .6-.3 .52 .52 0 0 1 .4 .6v.9h-.3v-.9a.36 .36 0 0 0-.4-.4 .36 .36 0 0 0-.3 .5v.8h-.2zM276.6 226.5a.92 .92 0 0 1 1.5 .3l-.2 .1a.72 .72 0 0 0-1-.3 .72 .72 0 0 0-.3 1 .79 .79 0 0 0 1.3 .2v-.3h-.6v-.3h.8v.8a1.08 1.08 0 0 1-1.5 0 1.08 1.08 0 0 1 0-1.5zM277.3 236.3h1.4v.3h-1.1v.6h1.1v.2h-1.1v.7h1.2v.2h-1.5zM276.4 229.8a.88 .88 0 0 1 1.5 .4h-.3a.65 .65 0 0 0-.9-.3 .65 .65 0 0 0-.3 .9 .62 .62 0 0 0 .5 .6 .62 .62 0 0 0 .7-.5l.3 .1a.95 .95 0 0 1-1.3 .6 .95 .95 0 0 1-.4-1.4zM277.7 219.5h1.4v.3h-1.2v.6h1.1v.2h-1.1v.7h1.3v.2h-1.5zM278.2 229.6h1.4v.2h-1.1v.7h.9v.2h-.9v.9h-.3zM279.1 236.3h.3l1.1 1.6v-1.6h.2v2h-.2l-1.1-1.5v1.5h-.3zM278.5 223.6a.54 .54 0 0 1 .8 0v-.7h.2v2h-.2v-.2a.6 .6 0 0 1-.7 .1 .6 .6 0 0 1-.3-.6h.2a.44 .44 0 0 0 .5 .5 .44 .44 0 0 0 .3-.7 .4 .4 0 0 0-.5-.4 .4 .4 0 0 0-.3 .6h-.2zM279.5 219.5h.4l.6 1.7 .6-1.7h.3v2h-.2v-1.6l-.6 1.6h-.2l-.6-1.7v1.7h-.3zM278.6 233.7a.54 .54 0 0 1 .8 0v-.7h.3v2h-.3v-.2a.6 .6 0 0 1-.7 .1 .6 .6 0 0 1-.3-.6h.3a.44 .44 0 0 0 .4 .5 .44 .44 0 0 0 .3-.7 .4 .4 0 0 0-.4-.4 .4 .4 0 0 0-.3 .6h-.3z"/>
<path d="M280.2 226.4l.3-.1a.73 .73 0 0 1 1 .5h-.2a.44 .44 0 0 0-.5-.4 .44 .44 0 0 0-.4 .5l.1 .1a1.18 1.18 0 0 1 1.1 .6 .8 .8 0 0 1-.8 .7 .8 .8 0 0 1-.8-.7h.2a.55 .55 0 0 0 .6 .5 .55 .55 0 0 0 .5-.5l-.2-.2a1.02 1.02 0 0 1-1-.5zM280.1 229.9a.92 .92 0 0 1 1.6 .3h-.3a.72 .72 0 0 0-1-.3 .72 .72 0 0 0-.2 1 .79 .79 0 0 0 1.2 .3v-.4h-.5v-.2h.8v.7a1.08 1.08 0 0 1-1.5 .1 1.08 1.08 0 0 1-.1-1.5zM281.3 232.9h.2a2.31 2.31 0 0 0 0 2.7h-.2a2.02 2.02 0 0 1 0-2.7zM281.8 232h1.7v.2h-1.7zM282 226.3h1.4v.2h-1.2v.6h1.1v.2h-1.1v.7h1.2v.3h-1.4zM280.9 223.1a.88 .88 0 0 1 1.5 .3l-.3 .1a.65 .65 0 0 0-.9-.3 .65 .65 0 0 0-.3 .8 .62 .62 0 0 0 .6 .7 .62 .62 0 0 0 .6-.5l.3 .1a.95 .95 0 0 1-1.3 .5 .95 .95 0 0 1-.4-1.3zM281.3 236.5a.64 .64 0 0 1 1 .1 .64 .64 0 0 1-.3 .9l-.6 .6h1v.2h-1.4a1.96 1.96 0 0 1 1-1.1 .39 .39 0 0 0-.1-.7 .39 .39 0 0 0-.6 .4h-.2zM282 220l.7-.5v2h-.3v-1.5l-.4 .3zM282.7 222.9h1.4v.2h-1.1v.7h.9v.2h-.9v.9h-.3zM282 233.2a.88 .88 0 0 1 1.5 .3l-.3 .1a.65 .65 0 0 0-.9-.4 .65 .65 0 0 0-.3 .9 .62 .62 0 0 0 .5 .7 .62 .62 0 0 0 .7-.5h.3a.95 .95 0 0 1-1.3 .6 .95 .95 0 0 1-.4-1.3zM283.8 229.8l.3-.2a.73 .73 0 0 1 1 .6h-.3a.44 .44 0 0 0-.4-.4 .44 .44 0 0 0-.4 .5 1.18 1.18 0 0 1 1.1 .6 .8 .8 0 0 1-.7 .8 .8 .8 0 0 1-.8-.7l.2-.1a.55 .55 0 0 0 .5 .5 .55 .55 0 0 0 .6-.4l-.2-.2a1.02 1.02 0 0 1-1.1-.6zM283.8 226.3h.3v1.7h1v.3h-1.3z"/>
<path d="M283.8 233h1.4v.2h-1.1v.6h.9v.3h-.9v.9h-.3zM283.4 236.9h1.4v.3h-1.4zM283.4 237.5h1.4v.3h-1.4zM284.6 223.1a.92 .92 0 0 1 1.6 .4h-.2a.72 .72 0 0 0-1.1-.3 .72 .72 0 0 0-.2 1 .79 .79 0 0 0 1.3 .3v-.4h-.6v-.2h.8v.7a1.08 1.08 0 0 1-1.5 .1 1.08 1.08 0 0 1-.1-1.6zM284.1 220.1h1.4v.3h-1.4zM284.1 220.7h1.4v.3h-1.4zM285.5 229.6h1.5v.2h-1.2v.7h1.1v.2h-1.1v.7h1.2v.2h-1.5zM285.9 236.3h.2v.8a.52 .52 0 0 1 .6-.2 .52 .52 0 0 1 .4 .5v.9h-.3v-.9a.36 .36 0 0 0-.4-.3 .36 .36 0 0 0-.3 .4v.8h-.2zM285.6 226.4a.71 .71 0 0 1 .8 0 .71 .71 0 0 1 .2 .9 .7 .7 0 0 1-.2 .8 .7 .7 0 0 1-.9 0l-.2-.8h.2a.56 .56 0 0 0 .5 .8 1.18 1.18 0 0 0 0-1.6 .43 .43 0 0 0-.5 .5v.3h-.2v-.6zM286.4 225.3h1.6v.2h-1.6zM285.7 233.2a.92 .92 0 0 1 1.6 .3l-.3 .1a.72 .72 0 0 0-1-.3 .72 .72 0 0 0-.2 1 .79 .79 0 0 0 1.2 .3v-.4h-.5v-.2h.8v.7a1.08 1.08 0 0 1-1.5 .1 1.08 1.08 0 0 1-.1-1.6zM286.6 219.5h.2v.8a.52 .52 0 0 1 .6-.2 .52 .52 0 0 1 .4 .5v.9h-.3v-.9a.36 .36 0 0 0-.4-.3 .36 .36 0 0 0-.3 .4v.8h-.2z"/>
<path d="M287.4 229.6h.2v1.8h1v.2h-1.2zM287.4 236.9h.3v1.4h-.3zM288.3 223l.3-.1a.73 .73 0 0 1 1 .6h-.2a.44 .44 0 0 0-.5-.4 .44 .44 0 0 0-.4 .5 1.19 1.19 0 0 1 1.2 .6 .8 .8 0 0 1-.8 .7 .8 .8 0 0 1-.8-.6l.2-.1a.55 .55 0 0 0 .5 .5 .55 .55 0 0 0 .6-.4l-.2-.2a1.02 1.02 0 0 1-1-.6zM288.1 220.1h.3v1.4h-.3zM288.2 237a.57 .57 0 0 1 .8 .1v-.2h.2v1.2a.63 .63 0 0 1-.4 .8 .63 .63 0 0 1-.8-.5l.3 .1a.4 .4 0 0 0 .5 .2 .4 .4 0 0 0 .2-.5 .61 .61 0 0 1-.7 .1 .61 .61 0 0 1-.3-.7h.2a.44 .44 0 0 0 .5 .5 .44 .44 0 0 0 .3-.6 .4 .4 0 0 0-.5-.4 .4 .4 0 0 0-.3 .5h-.2zM289.4 233.1l.3-.1a.73 .73 0 0 1 1 .5l-.3 .1a.44 .44 0 0 0-.4-.5 .44 .44 0 0 0-.4 .6 1.18 1.18 0 0 1 1.1 .6 .8 .8 0 0 1-.7 .7 .8 .8 0 0 1-.8-.7h.2a.55 .55 0 0 0 .5 .5 .55 .55 0 0 0 .6-.5l-.2-.1a1.02 1.02 0 0 1-1.1-.6zM288.9 220.2a.57 .57 0 0 1 .8 .1v-.2h.2v1.2a.63 .63 0 0 1-.4 .8 .63 .63 0 0 1-.8-.5l.2 .1a.4 .4 0 0 0 .6 .2 .4 .4 0 0 0 .2-.5 .61 .61 0 0 1-.7 .1 .61 .61 0 0 1-.3-.7h.2a.44 .44 0 0 0 .5 .5 .44 .44 0 0 0 .3-.6 .4 .4 0 0 0-.5-.4 .4 .4 0 0 0-.3 .5h-.2zM289.1 229.7a.71 .71 0 0 1 .9 .1 .71 .71 0 0 1 .1 .8 .7 .7 0 0 1-.2 .9 .7 .7 0 0 1-.9-.1l-.2-.8h.3a.56 .56 0 0 0 .5 .8 1.18 1.18 0 0 0 0-1.6 .43 .43 0 0 0-.5 .6v.2h-.3l.1-.5zM289.6 236.3h.3v.8a.52 .52 0 0 1 .6-.2 .52 .52 0 0 1 .3 .5v.9h-.3v-.9a.36 .36 0 0 0-.4-.3 .36 .36 0 0 0-.2 .4v.8h-.3zM290 222.9h1.5v.2h-1.2v.6h1.1v.3h-1.1v.7h1.2v.2h-1.5zM290.3 219.5h.3v.8a.52 .52 0 0 1 .6-.2 .52 .52 0 0 1 .3 .5v.9h-.3v-.9a.36 .36 0 0 0-.4-.3 .36 .36 0 0 0-.2 .4v.8h-.3zM291.1 233h1.5v.2h-1.2v.6h1.1v.3h-1.1v.6h1.2v.3h-1.5z"/>
<path d="M291.2 236.3h.1a2.02 2.02 0 0 1 0 2.6h-.1a2.31 2.31 0 0 0 0-2.6zM291.9 222.9h.3v1.8h.9v.2h-1.2zM290.9 226.9a.54 .54 0 0 1 .8 .1v-.7h.2v2h-.2v-.2a.6 .6 0 0 1-.7 .1 .6 .6 0 0 1-.3-.7h.2a.44 .44 0 0 0 .5 .6 .44 .44 0 0 0 .3-.7 .4 .4 0 0 0-.5-.4 .4 .4 0 0 0-.3 .5h-.2zM291.8 219.5h.2a2.02 2.02 0 0 1 0 2.6h-.2a2.31 2.31 0 0 0 0-2.6zM291.4 230.3a.65 .65 0 0 1 .8-.1 .65 .65 0 0 1 .2 .8l.1 .6h-.3v-.2a.57 .57 0 0 1-.6 .3 .57 .57 0 0 1-.4-.5h.2l.3 .3a.44 .44 0 0 0 .5-.6l-1 .3a.65 .65 0 0 1 .8-.5 .22 .22 0 0 0 .1-.3 .22 .22 0 0 0-.3-.1l-.2 .1-.2 .2h-.2zM292.8 230.2h.2v.2a.52 .52 0 0 1 .6-.2 .52 .52 0 0 1 .4 .5v.9h-.3v-.9a.36 .36 0 0 0-.4-.4 .36 .36 0 0 0-.3 .5v.8h-.2zM293 233h.2v1.7h1v.3h-1.2zM293.5 223.4l.8-.5v2h-.3v-1.6l-.5 .3zM293.3 226.5a.88 .88 0 0 1 1.5 .3l-.3 .1a.65 .65 0 0 0-.8-.4 .65 .65 0 0 0-.3 .9 .62 .62 0 0 0 .5 .7 .62 .62 0 0 0 .7-.5h.2a.95 .95 0 0 1-1.2 .6 .95 .95 0 0 1-.5-1.3zM295.2 226.3h1.3v.2h-1.1v.6h1v.2h-1v1h-.2zM294.7 233.1a.71 .71 0 0 1 .9 .1 .71 .71 0 0 1 .1 .8 .7 .7 0 0 1-.2 .8 .7 .7 0 0 1-.9 0l-.2-.8h.3a.56 .56 0 0 0 .5 .8 1.18 1.18 0 0 0 0-1.6 .43 .43 0 0 0-.5 .5v.3h-.3l.1-.6zM294.5 230.3a.54 .54 0 0 1 .8 0v-.7h.2v2h-.2v-.2a.6 .6 0 0 1-.7 .2 .6 .6 0 0 1-.3-.7h.2a.44 .44 0 0 0 .5 .5 .44 .44 0 0 0 .3-.6 .4 .4 0 0 0-.5-.5 .4 .4 0 0 0-.3 .6h-.2z"/>
<path d="M295.7 223.5h1.4v.2h-1.4zM295.7 224.1h1.4v.2h-1.4zM297.1 226.5a.92 .92 0 0 1 1.5 .3l-.2 .1a.72 .72 0 0 0-1-.3 .72 .72 0 0 0-.3 1 .79 .79 0 0 0 1.3 .2v-.3h-.6v-.3h.9v.8a1.08 1.08 0 0 1-1.6 0 1.08 1.08 0 0 1 0-1.5zM296.9 229.8a.88 .88 0 0 1 1.5 .4h-.3a.65 .65 0 0 0-.9-.3 .65 .65 0 0 0-.3 .9 .62 .62 0 0 0 .6 .6 .62 .62 0 0 0 .6-.5l.3 .1a.95 .95 0 0 1-1.3 .6 .95 .95 0 0 1-.4-1.4zM298.8 229.6h1.3v.2h-1.1v.7h1v.2h-1v.9h-.2zM298.9 223.6a.71 .71 0 0 1 1 .1 .71 .71 0 0 1-.1 1 .71 .71 0 0 1-1.1-.2v-.3h.3a.46 .46 0 0 0 .5 .5 .46 .46 0 0 0 .3-.7 .43 .43 0 0 0-.5-.4 .43 .43 0 0 0-.3 .6h-.3zM300.7 226.4l.3-.1a.73 .73 0 0 1 1.1 .5h-.3a.44 .44 0 0 0-.5-.4 .44 .44 0 0 0-.4 .5l.1 .1a1.19 1.19 0 0 1 1.1 .6 .8 .8 0 0 1-.8 .7 .8 .8 0 0 1-.8-.7h.3a.55 .55 0 0 0 .5 .5 .55 .55 0 0 0 .5-.5l-.2-.2a1.02 1.02 0 0 1-1-.5zM300.2 223.4h.2l.3 1.2 .3-1.2h.3l.3 1.2 .3-1.2h.3l-.5 1.5h-.2l-.3-1.1-.3 1.1h-.3zM300.1 233.7a.54 .54 0 0 1 .8 0v-.7h.2v2h-.2v-.2a.6 .6 0 0 1-.7 .1 .6 .6 0 0 1-.3-.6h.2a.44 .44 0 0 0 .5 .5 .44 .44 0 0 0 .3-.7 .4 .4 0 0 0-.5-.4 .4 .4 0 0 0-.3 .6h-.2zM300.7 229.9a.92 .92 0 0 1 1.5 .3h-.2a.72 .72 0 0 0-1-.3 .72 .72 0 0 0-.3 1 .79 .79 0 0 0 1.3 .3v-.4h-.6v-.2h.8v.7a1.08 1.08 0 0 1-1.5 .1 1.08 1.08 0 0 1 0-1.5zM302.4 232h1.6v.2h-1.6zM302.5 226.3h1.4v.2h-1.2v.6h1.2v.2h-1.2v.7h1.3v.3h-1.5z"/>
<path d="M302.4 222.9h.1a2.02 2.02 0 0 1 0 2.6h-.1a2.31 2.31 0 0 0 0-2.6zM302.5 233.2a.88 .88 0 0 1 1.5 .3l-.3 .1a.65 .65 0 0 0-.9-.4 .65 .65 0 0 0-.3 .9 .62 .62 0 0 0 .6 .7 .62 .62 0 0 0 .6-.5h.3a.95 .95 0 0 1-1.3 .6 .95 .95 0 0 1-.4-1.3zM304.3 229.8l.3-.2a.73 .73 0 0 1 1 .6h-.2a.44 .44 0 0 0-.5-.4 .44 .44 0 0 0-.4 .5h.1a1.18 1.18 0 0 1 1.1 .6 .8 .8 0 0 1-.8 .8 .8 .8 0 0 1-.8-.7l.2-.1a.55 .55 0 0 0 .6 .5 .55 .55 0 0 0 .5-.4l-.2-.2a1.02 1.02 0 0 1-1-.6zM304.3 226.3h.3v1.7h1v.3h-1.3zM304.4 233h1.3v.2h-1.1v.6h1v.3h-1v.9h-.2zM306.1 229.6h1.4v.2h-1.2v.7h1.1v.2h-1.1v.7h1.2v.2h-1.4zM306 226.7l.7-.5v2.1h-.2v-1.6l-.5 .3zM306.3 233.2a.92 .92 0 0 1 1.5 .3l-.2 .1a.72 .72 0 0 0-1-.3 .72 .72 0 0 0-.3 1 .79 .79 0 0 0 1.3 .3v-.4h-.6v-.2h.8v.7a1.08 1.08 0 0 1-1.5 .1 1.08 1.08 0 0 1 0-1.6zM307.9 229.6h.3v1.8h1v.2h-1.3zM309.9 233.1l.3-.1a.73 .73 0 0 1 1 .5l-.2 .1a.44 .44 0 0 0-.5-.5 .44 .44 0 0 0-.4 .6h.1a1.18 1.18 0 0 1 1.1 .6 .8 .8 0 0 1-.8 .7 .8 .8 0 0 1-.8-.7h.2a.55 .55 0 0 0 .6 .5 .55 .55 0 0 0 .5-.5l-.2-.1a1.02 1.02 0 0 1-1-.6zM309.6 230.1l.7-.5v2h-.3v-1.6l-.4 .3zM311.6 233h1.5v.2h-1.2v.6h1.1v.3h-1.1v.6h1.2v.3h-1.5z"/>
<path d="M311.7 230.8h1.4v.2h-1.4zM313.5 233h.3v1.7h1v.3h-1.3zM314.8 226.2h.2a2.02 2.02 0 0 1 0 2.6h-.2a2.31 2.31 0 0 0 0-2.6zM314.9 230.3a.71 .71 0 0 1 1.1 .1 .71 .71 0 0 1-.2 1.1 .71 .71 0 0 1-1-.3l-.1-.3h.3a.46 .46 0 0 0 .5 .5 .46 .46 0 0 0 .3-.7 .43 .43 0 0 0-.5-.4 .43 .43 0 0 0-.3 .6h-.3zM315.2 233.5l.7-.5v2h-.3v-1.6l-.4 .3zM316.2 230.2h.2l.4 1.1 .3-1.1h.2l.3 1.1 .3-1.1h.3l-.5 1.4h-.2l-.3-1.1-.3 1.1h-.3zM318.4 229.6h.1a2.02 2.02 0 0 1 0 2.6h-.1a2.31 2.31 0 0 0 0-2.6zM317.3 233.6h1.4v.2h-1.4zM324 232.9h.1a2.02 2.02 0 0 1 0 2.7h-.1a2.31 2.31 0 0 0 0-2.7z"/>
</g>
<g fill="none" stroke="#000" stroke-width=".25">
<path d="M233.1 216.2v2M233.7 216.2v2M248.4 219.5v2M263.4 216.2v2M265.3 219.5v2M278.2 216.2v2M234.8 226.3v2M237.9 236.3v2M242.5 229.6v2M242.5 233v2M254.8 222.9v2M267.3 226.3v2"/>
<path d="M270.8 229.6v2M276.4 233v2M298.3 222.9v2M310.7 226.3v2M314.3 229.6v2M319.9 233v2"/>
</g>
<path d="M231.4 229.6v2M231.4 233v2" fill="none" stroke="#000" stroke-width=".27"/>
<g fill="#0000c2">
<path d="M222.1 68.1a.52 .52 0 0 1 .6 .3 .52 .52 0 0 1-.3 .7l-.4 .1 .3-.2 .2-.3h-.4a.2 .2 0 0 1-.1-.2 .2 .2 0 0 1 .1-.2 .26 .26 0 0 0 .1 .3 .26 .26 0 0 0 .4-.1 .26 .26 0 0 0-.1-.3l-.2-.2-.2 .3h-.1z"/>
<path d="M223 68.1l.1-.1a.6 .6 0 0 1 .6 .5 .6 .6 0 0 1-.4 .7h-.2l-.2-.2-.1-.4h.2a.3 .3 0 0 0 0 .4 .3 .3 0 0 0 .3 .1l.1-.7-.1-.4a.36 .36 0 0 0-.3 .6h-.2z"/>
<path d="M224.4 68.1a.59 .59 0 0 1 .9 .2 .59 .59 0 0 1-.4 .8 .59 .59 0 0 1-.7-.5h.2a.42 .42 0 0 0 .4 .5 .42 .42 0 0 0 .3-.6 .39 .39 0 0 0-.4-.5 .39 .39 0 0 0-.3 .6h-.2z"/>
<path d="M225.4 68l.3-.1v.6l.2-.1h.2l.2 .8h-.4l.1-.2v-.5h-.1l-.2 .1v.5l.1 .1h-.4l.1-.1v-.8z"/>
<path d="M226.3 68.5l.3-.1v.1l.2-.1 .2 .1 .4-.1 .2 .8h-.3l.1-.1v-.4l-.1-.2-.3 .1 .1 .5 .1 .1h-.4l.1-.1v-.4l-.1-.2-.2 .1v.5l.1 .1h-.4l.1-.5z"/>
<path d="M228.1 68.6h.4l.1-.5v.5h.4h-.4v.4l.4 .1h-.9l.4-.1v-.4z"/>
<path d="M326.2 68.1a.52 .52 0 0 1 .7 .3 .52 .52 0 0 1-.3 .7l-.5 .1 .3-.2 .2-.3h-.4a.2 .2 0 0 1-.1-.2 .2 .2 0 0 1 .1-.2 .26 .26 0 0 0 .2 .3 .26 .26 0 0 0 .3-.1 .26 .26 0 0 0-.1-.3l-.2-.2-.2 .3h-.1z"/>
<path d="M327.1 68.1l.1-.1a.6 .6 0 0 1 .6 .5 .6 .6 0 0 1-.3 .7h-.3l-.1-.2-.1-.4h.1a.3 .3 0 0 0 0 .4 .3 .3 0 0 0 .3 .1l.2-.7-.2-.4a.36 .36 0 0 0-.3 .6h-.1z"/>
<path d="M328.5 68.1a.59 .59 0 0 1 .9 .2 .59 .59 0 0 1-.3 .8 .59 .59 0 0 1-.8-.5h.2a.42 .42 0 0 0 .5 .5 .42 .42 0 0 0 .3-.6 .39 .39 0 0 0-.5-.5 .39 .39 0 0 0-.3 .6h-.2z"/>
<path d="M329.5 68l.3-.1v.6l.2-.1h.2l.2 .8h-.4l.1-.2v-.5h-.1l-.2 .1v.5l.1 .1h-.4l.2-.1v-.8z"/>
<path d="M330.4 68.5l.3-.1v.1l.3-.1 .2 .1 .4-.1 .2 .8h-.4l.1-.1v-.4l-.1-.2-.2 .1v.5l.1 .1h-.4l.1-.1v-.4l-.1-.2-.2 .1v.5l.1 .1h-.4l.2-.5z"/>
<path d="M332.2 68.6h.5v-.5v.5h.5h-.5v.4l.5 .1h-1l.5-.1v-.4z"/>
<path d="M144 65.6l.2-.1v.6l.2-.2 .2 .1 .2 .8h-.4l.2-.2v-.5l-.2-.1-.2 .1v.6l.2 .1h-.4l.1-.2v-.8z"/>
<path d="M140.4 67.7l.2-.1v.5l.2-.1h.2l.2 .8h-.4l.2-.2-.1-.4-.1-.1-.2 .1v.5l.2 .1h-.4l.1-.1v-.8z"/>
<path d="M148.2 67.7l.2-.1v.5l.2-.1h.2l.2 .8h-.4l.2-.2-.1-.4-.1-.1-.2 .1v.5l.2 .1h-.4l.1-.1v-.8z"/>
<path d="M149.5 69.7l.2 .1-.1 .7z"/>
<circle cx="149.9" cy="65.6" r=".09"/>
<circle cx="336.3" cy="205" r=".09"/>
</g>
<g fill="none" stroke="#000" stroke-width=".18">
<path d="M363.2 29.2h2.6M368.3 34.3v2.5M370.8 29.2h2.6M370.8 39.4h.8M375.2 39.4h.7M25.4 72.4h3.8M25.4 69.9h3.8M25.4 67.3h3.8M106.7 72.4v2.5M109.2 68.6h.1M50.8 92.7h.8M55.1 92.7h.8"/>
<path d="M63.5 99.1v2.5M64.8 92.7h2.5M64.8 90.2h2.5M69.8 85.1v2.5M69.8 95.3v2.5M72.4 92.7h2.5M72.4 90.2h2.5M94 87.6h2.5M94 92.7h2.5M94 97.8h2.5M111.8 82.6h2.5M111.8 87.6h2.5"/>
<path d="M111.8 92.7h2.5M111.8 97.8h2.5M63.5 104.1v2.6M104.1 105.4v2.6M257.7 142.5h5.2M321.3 185.4v2.1M321.3 188.5v2M83.8 219.7h.1M94 219.7h.1M71.1 233.7h3.8M86.4 226.1v3.8M91.4 226.1v3.8"/>
<path d="M99.3 237.7h2.9M102.9 233.7h3.8M102.9 236.2h3.8M102.9 238.8h3.8M71.1 241.3h3.8M71.1 243.8h3.8M71.1 248.9h3.8M75.6 247.9h5.1M86.4 257.8v3.8M88.9 257.8v3.8M91.4 257.8v3.8M99.2 240.3h3"/>
<path d="M102.9 241.3h3.8M102.9 248.9h3.8M102.9 246.4h3.8M102.9 251.5h3.8M102.9 254h3.8"/>
</g>
<g fill="#000" stroke="#000" stroke-width=".18">
<circle cx="29.2" cy="29.2" r=".46"/>
<circle cx="59.7" cy="29.2" r=".46"/>
<circle cx="116.8" cy="29.2" r=".46"/>
<circle cx="127" cy="29.2" r=".46"/>
<circle cx="221" cy="29.2" r=".46"/>
<circle cx="350.5" cy="29.2" r=".46"/>
<circle cx="358.1" cy="29.2" r=".46"/>
<circle cx="368.3" cy="39.4" r=".46"/>
<circle cx="378.5" cy="29.2" r=".46"/>
<circle cx="386.1" cy="29.2" r=".46"/>
<circle cx="196.8" cy="43.2" r=".46"/>
<circle cx="196.8" cy="48.3" r=".46"/>
<circle cx="280.7" cy="43.2" r=".46"/>
<circle cx="280.7" cy="48.3" r=".46"/>
<circle cx="281.9" cy="54.6" r=".46"/>
<circle cx="284.5" cy="57.2" r=".46"/>
<circle cx="368.3" cy="50.8" r=".46"/>
<circle cx="30.5" cy="69.9" r=".46"/>
<circle cx="63.5" cy="69.9" r=".46"/>
<circle cx="69.8" cy="69.9" r=".46"/>
<circle cx="69.8" cy="61" r=".46"/>
<circle cx="87.6" cy="61" r=".46"/>
<circle cx="109.2" cy="61" r=".46"/>
<circle cx="125.7" cy="68.6" r=".46"/>
<circle cx="63.5" cy="82.6" r=".46"/>
<circle cx="86.4" cy="97.8" r=".46"/>
<circle cx="88.9" cy="92.7" r=".46"/>
<circle cx="91.4" cy="87.6" r=".46"/>
<circle cx="91.4" cy="82.6" r=".46"/>
<circle cx="116.8" cy="87.6" r=".46"/>
<circle cx="208.3" cy="94" r=".46"/>
<circle cx="280.7" cy="86.4" r=".46"/>
<circle cx="312.4" cy="90.2" r=".46"/>
<circle cx="247.6" cy="129.5" r=".46"/>
<circle cx="285.7" cy="121.9" r=".46"/>
<circle cx="287" cy="121.9" r=".46"/>
<circle cx="288.3" cy="121.9" r=".46"/>
<circle cx="226.1" cy="156.2" r=".46"/>
<circle cx="190.5" cy="170.2" r=".46"/>
<circle cx="218.4" cy="179.1" r=".46"/>
<circle cx="219.7" cy="166.4" r=".46"/>
<circle cx="234.9" cy="179.1" r=".46"/>
<circle cx="252.7" cy="177.8" r=".46"/>
<circle cx="252.7" cy="175.3" r=".46"/>
<circle cx="204.5" cy="184.2" r=".46"/>
<circle cx="218.4" cy="189.2" r=".46"/>
<circle cx="234.9" cy="189.2" r=".46"/>
<circle cx="69.8" cy="212.1" r=".46"/>
<circle cx="83.8" cy="212.1" r=".46"/>
<circle cx="94" cy="212.1" r=".46"/>
<circle cx="20.3" cy="227.3" r=".46"/>
<circle cx="35.6" cy="227.3" r=".46"/>
<circle cx="120.6" cy="233.7" r=".46"/>
<circle cx="125.7" cy="236.2" r=".46"/>
<circle cx="64.8" cy="261.6" r=".46"/>
<circle cx="88.9" cy="262.9" r=".46"/>
</g>
<g fill="#008484" stroke="#008484" stroke-width=".18">
<circle cx="280.7" cy="64.8" r=".46"/>
<circle cx="283.2" cy="77.5" r=".46"/>
<circle cx="119.4" cy="92.7" r=".46"/>
<circle cx="121.9" cy="97.8" r=".46"/>
</g>
<use href="#words"/>
</svg>
